VERSION 5.8 ;
BUSBITCHARS "[]" ;
DIVIDERCHAR "/" ;

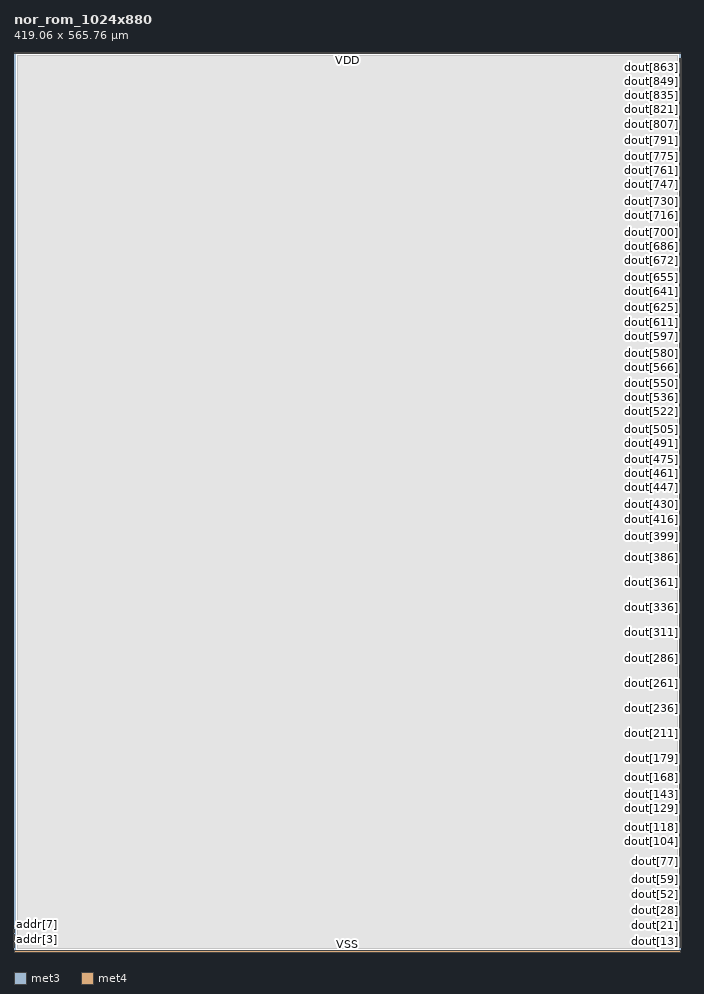
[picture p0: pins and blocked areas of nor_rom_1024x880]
MACRO nor_rom_1024x880
  CLASS BLOCK ;
  ORIGIN 0 0 ;
  SIZE 419.060 BY 565.760 ;
  SYMMETRY X Y ;

  PIN clk
    DIRECTION INPUT ;
    USE CLOCK ;
    PORT
      LAYER met3 ;
        RECT -0.500 3.000 0.500 3.280 ;
    END
  END clk

  PIN ce
    DIRECTION INPUT ;
    USE SIGNAL ;
    PORT
      LAYER met3 ;
        RECT -0.500 4.000 0.500 4.280 ;
    END
  END ce

  PIN addr[0]
    DIRECTION INPUT ;
    USE SIGNAL ;
    PORT
      LAYER met3 ;
        RECT -0.500 5.000 0.500 5.280 ;
    END
  END addr[0]

  PIN addr[1]
    DIRECTION INPUT ;
    USE SIGNAL ;
    PORT
      LAYER met3 ;
        RECT -0.500 6.000 0.500 6.280 ;
    END
  END addr[1]

  PIN addr[2]
    DIRECTION INPUT ;
    USE SIGNAL ;
    PORT
      LAYER met3 ;
        RECT -0.500 7.000 0.500 7.280 ;
    END
  END addr[2]

  PIN addr[3]
    DIRECTION INPUT ;
    USE SIGNAL ;
    PORT
      LAYER met3 ;
        RECT -0.500 8.000 0.500 8.280 ;
    END
  END addr[3]

  PIN addr[4]
    DIRECTION INPUT ;
    USE SIGNAL ;
    PORT
      LAYER met3 ;
        RECT -0.500 9.000 0.500 9.280 ;
    END
  END addr[4]

  PIN addr[5]
    DIRECTION INPUT ;
    USE SIGNAL ;
    PORT
      LAYER met3 ;
        RECT -0.500 10.000 0.500 10.280 ;
    END
  END addr[5]

  PIN addr[6]
    DIRECTION INPUT ;
    USE SIGNAL ;
    PORT
      LAYER met3 ;
        RECT -0.500 11.000 0.500 11.280 ;
    END
  END addr[6]

  PIN addr[7]
    DIRECTION INPUT ;
    USE SIGNAL ;
    PORT
      LAYER met3 ;
        RECT -0.500 12.000 0.500 12.280 ;
    END
  END addr[7]

  PIN addr[8]
    DIRECTION INPUT ;
    USE SIGNAL ;
    PORT
      LAYER met3 ;
        RECT -0.500 13.000 0.500 13.280 ;
    END
  END addr[8]

  PIN addr[9]
    DIRECTION INPUT ;
    USE SIGNAL ;
    PORT
      LAYER met3 ;
        RECT -0.500 14.000 0.500 14.280 ;
    END
  END addr[9]

  PIN dout[0]
    DIRECTION OUTPUT ;
    USE SIGNAL ;
    PORT
      LAYER met3 ;
        RECT 418.560 3.000 419.560 3.280 ;
    END
  END dout[0]

  PIN dout[1]
    DIRECTION OUTPUT ;
    USE SIGNAL ;
    PORT
      LAYER met3 ;
        RECT 418.560 3.635 419.560 3.915 ;
    END
  END dout[1]

  PIN dout[2]
    DIRECTION OUTPUT ;
    USE SIGNAL ;
    PORT
      LAYER met3 ;
        RECT 418.560 4.270 419.560 4.550 ;
    END
  END dout[2]

  PIN dout[3]
    DIRECTION OUTPUT ;
    USE SIGNAL ;
    PORT
      LAYER met3 ;
        RECT 418.560 4.905 419.560 5.185 ;
    END
  END dout[3]

  PIN dout[4]
    DIRECTION OUTPUT ;
    USE SIGNAL ;
    PORT
      LAYER met3 ;
        RECT 418.560 5.540 419.560 5.820 ;
    END
  END dout[4]

  PIN dout[5]
    DIRECTION OUTPUT ;
    USE SIGNAL ;
    PORT
      LAYER met3 ;
        RECT 418.560 6.175 419.560 6.455 ;
    END
  END dout[5]

  PIN dout[6]
    DIRECTION OUTPUT ;
    USE SIGNAL ;
    PORT
      LAYER met3 ;
        RECT 418.560 6.810 419.560 7.090 ;
    END
  END dout[6]

  PIN dout[7]
    DIRECTION OUTPUT ;
    USE SIGNAL ;
    PORT
      LAYER met3 ;
        RECT 418.560 7.445 419.560 7.725 ;
    END
  END dout[7]

  PIN dout[8]
    DIRECTION OUTPUT ;
    USE SIGNAL ;
    PORT
      LAYER met3 ;
        RECT 418.560 8.080 419.560 8.360 ;
    END
  END dout[8]

  PIN dout[9]
    DIRECTION OUTPUT ;
    USE SIGNAL ;
    PORT
      LAYER met3 ;
        RECT 418.560 8.715 419.560 8.995 ;
    END
  END dout[9]

  PIN dout[10]
    DIRECTION OUTPUT ;
    USE SIGNAL ;
    PORT
      LAYER met3 ;
        RECT 418.560 9.350 419.560 9.630 ;
    END
  END dout[10]

  PIN dout[11]
    DIRECTION OUTPUT ;
    USE SIGNAL ;
    PORT
      LAYER met3 ;
        RECT 418.560 9.985 419.560 10.265 ;
    END
  END dout[11]

  PIN dout[12]
    DIRECTION OUTPUT ;
    USE SIGNAL ;
    PORT
      LAYER met3 ;
        RECT 418.560 10.620 419.560 10.900 ;
    END
  END dout[12]

  PIN dout[13]
    DIRECTION OUTPUT ;
    USE SIGNAL ;
    PORT
      LAYER met3 ;
        RECT 418.560 11.255 419.560 11.535 ;
    END
  END dout[13]

  PIN dout[14]
    DIRECTION OUTPUT ;
    USE SIGNAL ;
    PORT
      LAYER met3 ;
        RECT 418.560 11.890 419.560 12.170 ;
    END
  END dout[14]

  PIN dout[15]
    DIRECTION OUTPUT ;
    USE SIGNAL ;
    PORT
      LAYER met3 ;
        RECT 418.560 12.525 419.560 12.805 ;
    END
  END dout[15]

  PIN dout[16]
    DIRECTION OUTPUT ;
    USE SIGNAL ;
    PORT
      LAYER met3 ;
        RECT 418.560 13.160 419.560 13.440 ;
    END
  END dout[16]

  PIN dout[17]
    DIRECTION OUTPUT ;
    USE SIGNAL ;
    PORT
      LAYER met3 ;
        RECT 418.560 13.795 419.560 14.075 ;
    END
  END dout[17]

  PIN dout[18]
    DIRECTION OUTPUT ;
    USE SIGNAL ;
    PORT
      LAYER met3 ;
        RECT 418.560 14.430 419.560 14.710 ;
    END
  END dout[18]

  PIN dout[19]
    DIRECTION OUTPUT ;
    USE SIGNAL ;
    PORT
      LAYER met3 ;
        RECT 418.560 15.065 419.560 15.345 ;
    END
  END dout[19]

  PIN dout[20]
    DIRECTION OUTPUT ;
    USE SIGNAL ;
    PORT
      LAYER met3 ;
        RECT 418.560 15.700 419.560 15.980 ;
    END
  END dout[20]

  PIN dout[21]
    DIRECTION OUTPUT ;
    USE SIGNAL ;
    PORT
      LAYER met3 ;
        RECT 418.560 16.335 419.560 16.615 ;
    END
  END dout[21]

  PIN dout[22]
    DIRECTION OUTPUT ;
    USE SIGNAL ;
    PORT
      LAYER met3 ;
        RECT 418.560 16.970 419.560 17.250 ;
    END
  END dout[22]

  PIN dout[23]
    DIRECTION OUTPUT ;
    USE SIGNAL ;
    PORT
      LAYER met3 ;
        RECT 418.560 17.605 419.560 17.885 ;
    END
  END dout[23]

  PIN dout[24]
    DIRECTION OUTPUT ;
    USE SIGNAL ;
    PORT
      LAYER met3 ;
        RECT 418.560 18.240 419.560 18.520 ;
    END
  END dout[24]

  PIN dout[25]
    DIRECTION OUTPUT ;
    USE SIGNAL ;
    PORT
      LAYER met3 ;
        RECT 418.560 18.875 419.560 19.155 ;
    END
  END dout[25]

  PIN dout[26]
    DIRECTION OUTPUT ;
    USE SIGNAL ;
    PORT
      LAYER met3 ;
        RECT 418.560 19.510 419.560 19.790 ;
    END
  END dout[26]

  PIN dout[27]
    DIRECTION OUTPUT ;
    USE SIGNAL ;
    PORT
      LAYER met3 ;
        RECT 418.560 20.145 419.560 20.425 ;
    END
  END dout[27]

  PIN dout[28]
    DIRECTION OUTPUT ;
    USE SIGNAL ;
    PORT
      LAYER met3 ;
        RECT 418.560 20.780 419.560 21.060 ;
    END
  END dout[28]

  PIN dout[29]
    DIRECTION OUTPUT ;
    USE SIGNAL ;
    PORT
      LAYER met3 ;
        RECT 418.560 21.415 419.560 21.695 ;
    END
  END dout[29]

  PIN dout[30]
    DIRECTION OUTPUT ;
    USE SIGNAL ;
    PORT
      LAYER met3 ;
        RECT 418.560 22.050 419.560 22.330 ;
    END
  END dout[30]

  PIN dout[31]
    DIRECTION OUTPUT ;
    USE SIGNAL ;
    PORT
      LAYER met3 ;
        RECT 418.560 22.685 419.560 22.965 ;
    END
  END dout[31]

  PIN dout[32]
    DIRECTION OUTPUT ;
    USE SIGNAL ;
    PORT
      LAYER met3 ;
        RECT 418.560 23.320 419.560 23.600 ;
    END
  END dout[32]

  PIN dout[33]
    DIRECTION OUTPUT ;
    USE SIGNAL ;
    PORT
      LAYER met3 ;
        RECT 418.560 23.955 419.560 24.235 ;
    END
  END dout[33]

  PIN dout[34]
    DIRECTION OUTPUT ;
    USE SIGNAL ;
    PORT
      LAYER met3 ;
        RECT 418.560 24.590 419.560 24.870 ;
    END
  END dout[34]

  PIN dout[35]
    DIRECTION OUTPUT ;
    USE SIGNAL ;
    PORT
      LAYER met3 ;
        RECT 418.560 25.225 419.560 25.505 ;
    END
  END dout[35]

  PIN dout[36]
    DIRECTION OUTPUT ;
    USE SIGNAL ;
    PORT
      LAYER met3 ;
        RECT 418.560 25.860 419.560 26.140 ;
    END
  END dout[36]

  PIN dout[37]
    DIRECTION OUTPUT ;
    USE SIGNAL ;
    PORT
      LAYER met3 ;
        RECT 418.560 26.495 419.560 26.775 ;
    END
  END dout[37]

  PIN dout[38]
    DIRECTION OUTPUT ;
    USE SIGNAL ;
    PORT
      LAYER met3 ;
        RECT 418.560 27.130 419.560 27.410 ;
    END
  END dout[38]

  PIN dout[39]
    DIRECTION OUTPUT ;
    USE SIGNAL ;
    PORT
      LAYER met3 ;
        RECT 418.560 27.765 419.560 28.045 ;
    END
  END dout[39]

  PIN dout[40]
    DIRECTION OUTPUT ;
    USE SIGNAL ;
    PORT
      LAYER met3 ;
        RECT 418.560 28.400 419.560 28.680 ;
    END
  END dout[40]

  PIN dout[41]
    DIRECTION OUTPUT ;
    USE SIGNAL ;
    PORT
      LAYER met3 ;
        RECT 418.560 29.035 419.560 29.315 ;
    END
  END dout[41]

  PIN dout[42]
    DIRECTION OUTPUT ;
    USE SIGNAL ;
    PORT
      LAYER met3 ;
        RECT 418.560 29.670 419.560 29.950 ;
    END
  END dout[42]

  PIN dout[43]
    DIRECTION OUTPUT ;
    USE SIGNAL ;
    PORT
      LAYER met3 ;
        RECT 418.560 30.305 419.560 30.585 ;
    END
  END dout[43]

  PIN dout[44]
    DIRECTION OUTPUT ;
    USE SIGNAL ;
    PORT
      LAYER met3 ;
        RECT 418.560 30.940 419.560 31.220 ;
    END
  END dout[44]

  PIN dout[45]
    DIRECTION OUTPUT ;
    USE SIGNAL ;
    PORT
      LAYER met3 ;
        RECT 418.560 31.575 419.560 31.855 ;
    END
  END dout[45]

  PIN dout[46]
    DIRECTION OUTPUT ;
    USE SIGNAL ;
    PORT
      LAYER met3 ;
        RECT 418.560 32.210 419.560 32.490 ;
    END
  END dout[46]

  PIN dout[47]
    DIRECTION OUTPUT ;
    USE SIGNAL ;
    PORT
      LAYER met3 ;
        RECT 418.560 32.845 419.560 33.125 ;
    END
  END dout[47]

  PIN dout[48]
    DIRECTION OUTPUT ;
    USE SIGNAL ;
    PORT
      LAYER met3 ;
        RECT 418.560 33.480 419.560 33.760 ;
    END
  END dout[48]

  PIN dout[49]
    DIRECTION OUTPUT ;
    USE SIGNAL ;
    PORT
      LAYER met3 ;
        RECT 418.560 34.115 419.560 34.395 ;
    END
  END dout[49]

  PIN dout[50]
    DIRECTION OUTPUT ;
    USE SIGNAL ;
    PORT
      LAYER met3 ;
        RECT 418.560 34.750 419.560 35.030 ;
    END
  END dout[50]

  PIN dout[51]
    DIRECTION OUTPUT ;
    USE SIGNAL ;
    PORT
      LAYER met3 ;
        RECT 418.560 35.385 419.560 35.665 ;
    END
  END dout[51]

  PIN dout[52]
    DIRECTION OUTPUT ;
    USE SIGNAL ;
    PORT
      LAYER met3 ;
        RECT 418.560 36.020 419.560 36.300 ;
    END
  END dout[52]

  PIN dout[53]
    DIRECTION OUTPUT ;
    USE SIGNAL ;
    PORT
      LAYER met3 ;
        RECT 418.560 36.655 419.560 36.935 ;
    END
  END dout[53]

  PIN dout[54]
    DIRECTION OUTPUT ;
    USE SIGNAL ;
    PORT
      LAYER met3 ;
        RECT 418.560 37.290 419.560 37.570 ;
    END
  END dout[54]

  PIN dout[55]
    DIRECTION OUTPUT ;
    USE SIGNAL ;
    PORT
      LAYER met3 ;
        RECT 418.560 37.925 419.560 38.205 ;
    END
  END dout[55]

  PIN dout[56]
    DIRECTION OUTPUT ;
    USE SIGNAL ;
    PORT
      LAYER met3 ;
        RECT 418.560 38.560 419.560 38.840 ;
    END
  END dout[56]

  PIN dout[57]
    DIRECTION OUTPUT ;
    USE SIGNAL ;
    PORT
      LAYER met3 ;
        RECT 418.560 39.195 419.560 39.475 ;
    END
  END dout[57]

  PIN dout[58]
    DIRECTION OUTPUT ;
    USE SIGNAL ;
    PORT
      LAYER met3 ;
        RECT 418.560 39.830 419.560 40.110 ;
    END
  END dout[58]

  PIN dout[59]
    DIRECTION OUTPUT ;
    USE SIGNAL ;
    PORT
      LAYER met3 ;
        RECT 418.560 40.465 419.560 40.745 ;
    END
  END dout[59]

  PIN dout[60]
    DIRECTION OUTPUT ;
    USE SIGNAL ;
    PORT
      LAYER met3 ;
        RECT 418.560 41.100 419.560 41.380 ;
    END
  END dout[60]

  PIN dout[61]
    DIRECTION OUTPUT ;
    USE SIGNAL ;
    PORT
      LAYER met3 ;
        RECT 418.560 41.735 419.560 42.015 ;
    END
  END dout[61]

  PIN dout[62]
    DIRECTION OUTPUT ;
    USE SIGNAL ;
    PORT
      LAYER met3 ;
        RECT 418.560 42.370 419.560 42.650 ;
    END
  END dout[62]

  PIN dout[63]
    DIRECTION OUTPUT ;
    USE SIGNAL ;
    PORT
      LAYER met3 ;
        RECT 418.560 43.005 419.560 43.285 ;
    END
  END dout[63]

  PIN dout[64]
    DIRECTION OUTPUT ;
    USE SIGNAL ;
    PORT
      LAYER met3 ;
        RECT 418.560 43.640 419.560 43.920 ;
    END
  END dout[64]

  PIN dout[65]
    DIRECTION OUTPUT ;
    USE SIGNAL ;
    PORT
      LAYER met3 ;
        RECT 418.560 44.275 419.560 44.555 ;
    END
  END dout[65]

  PIN dout[66]
    DIRECTION OUTPUT ;
    USE SIGNAL ;
    PORT
      LAYER met3 ;
        RECT 418.560 44.910 419.560 45.190 ;
    END
  END dout[66]

  PIN dout[67]
    DIRECTION OUTPUT ;
    USE SIGNAL ;
    PORT
      LAYER met3 ;
        RECT 418.560 45.545 419.560 45.825 ;
    END
  END dout[67]

  PIN dout[68]
    DIRECTION OUTPUT ;
    USE SIGNAL ;
    PORT
      LAYER met3 ;
        RECT 418.560 46.180 419.560 46.460 ;
    END
  END dout[68]

  PIN dout[69]
    DIRECTION OUTPUT ;
    USE SIGNAL ;
    PORT
      LAYER met3 ;
        RECT 418.560 46.815 419.560 47.095 ;
    END
  END dout[69]

  PIN dout[70]
    DIRECTION OUTPUT ;
    USE SIGNAL ;
    PORT
      LAYER met3 ;
        RECT 418.560 47.450 419.560 47.730 ;
    END
  END dout[70]

  PIN dout[71]
    DIRECTION OUTPUT ;
    USE SIGNAL ;
    PORT
      LAYER met3 ;
        RECT 418.560 48.085 419.560 48.365 ;
    END
  END dout[71]

  PIN dout[72]
    DIRECTION OUTPUT ;
    USE SIGNAL ;
    PORT
      LAYER met3 ;
        RECT 418.560 48.720 419.560 49.000 ;
    END
  END dout[72]

  PIN dout[73]
    DIRECTION OUTPUT ;
    USE SIGNAL ;
    PORT
      LAYER met3 ;
        RECT 418.560 49.355 419.560 49.635 ;
    END
  END dout[73]

  PIN dout[74]
    DIRECTION OUTPUT ;
    USE SIGNAL ;
    PORT
      LAYER met3 ;
        RECT 418.560 49.990 419.560 50.270 ;
    END
  END dout[74]

  PIN dout[75]
    DIRECTION OUTPUT ;
    USE SIGNAL ;
    PORT
      LAYER met3 ;
        RECT 418.560 50.625 419.560 50.905 ;
    END
  END dout[75]

  PIN dout[76]
    DIRECTION OUTPUT ;
    USE SIGNAL ;
    PORT
      LAYER met3 ;
        RECT 418.560 51.260 419.560 51.540 ;
    END
  END dout[76]

  PIN dout[77]
    DIRECTION OUTPUT ;
    USE SIGNAL ;
    PORT
      LAYER met3 ;
        RECT 418.560 51.895 419.560 52.175 ;
    END
  END dout[77]

  PIN dout[78]
    DIRECTION OUTPUT ;
    USE SIGNAL ;
    PORT
      LAYER met3 ;
        RECT 418.560 52.530 419.560 52.810 ;
    END
  END dout[78]

  PIN dout[79]
    DIRECTION OUTPUT ;
    USE SIGNAL ;
    PORT
      LAYER met3 ;
        RECT 418.560 53.165 419.560 53.445 ;
    END
  END dout[79]

  PIN dout[80]
    DIRECTION OUTPUT ;
    USE SIGNAL ;
    PORT
      LAYER met3 ;
        RECT 418.560 53.800 419.560 54.080 ;
    END
  END dout[80]

  PIN dout[81]
    DIRECTION OUTPUT ;
    USE SIGNAL ;
    PORT
      LAYER met3 ;
        RECT 418.560 54.435 419.560 54.715 ;
    END
  END dout[81]

  PIN dout[82]
    DIRECTION OUTPUT ;
    USE SIGNAL ;
    PORT
      LAYER met3 ;
        RECT 418.560 55.070 419.560 55.350 ;
    END
  END dout[82]

  PIN dout[83]
    DIRECTION OUTPUT ;
    USE SIGNAL ;
    PORT
      LAYER met3 ;
        RECT 418.560 55.705 419.560 55.985 ;
    END
  END dout[83]

  PIN dout[84]
    DIRECTION OUTPUT ;
    USE SIGNAL ;
    PORT
      LAYER met3 ;
        RECT 418.560 56.340 419.560 56.620 ;
    END
  END dout[84]

  PIN dout[85]
    DIRECTION OUTPUT ;
    USE SIGNAL ;
    PORT
      LAYER met3 ;
        RECT 418.560 56.975 419.560 57.255 ;
    END
  END dout[85]

  PIN dout[86]
    DIRECTION OUTPUT ;
    USE SIGNAL ;
    PORT
      LAYER met3 ;
        RECT 418.560 57.610 419.560 57.890 ;
    END
  END dout[86]

  PIN dout[87]
    DIRECTION OUTPUT ;
    USE SIGNAL ;
    PORT
      LAYER met3 ;
        RECT 418.560 58.245 419.560 58.525 ;
    END
  END dout[87]

  PIN dout[88]
    DIRECTION OUTPUT ;
    USE SIGNAL ;
    PORT
      LAYER met3 ;
        RECT 418.560 58.880 419.560 59.160 ;
    END
  END dout[88]

  PIN dout[89]
    DIRECTION OUTPUT ;
    USE SIGNAL ;
    PORT
      LAYER met3 ;
        RECT 418.560 59.515 419.560 59.795 ;
    END
  END dout[89]

  PIN dout[90]
    DIRECTION OUTPUT ;
    USE SIGNAL ;
    PORT
      LAYER met3 ;
        RECT 418.560 60.150 419.560 60.430 ;
    END
  END dout[90]

  PIN dout[91]
    DIRECTION OUTPUT ;
    USE SIGNAL ;
    PORT
      LAYER met3 ;
        RECT 418.560 60.785 419.560 61.065 ;
    END
  END dout[91]

  PIN dout[92]
    DIRECTION OUTPUT ;
    USE SIGNAL ;
    PORT
      LAYER met3 ;
        RECT 418.560 61.420 419.560 61.700 ;
    END
  END dout[92]

  PIN dout[93]
    DIRECTION OUTPUT ;
    USE SIGNAL ;
    PORT
      LAYER met3 ;
        RECT 418.560 62.055 419.560 62.335 ;
    END
  END dout[93]

  PIN dout[94]
    DIRECTION OUTPUT ;
    USE SIGNAL ;
    PORT
      LAYER met3 ;
        RECT 418.560 62.690 419.560 62.970 ;
    END
  END dout[94]

  PIN dout[95]
    DIRECTION OUTPUT ;
    USE SIGNAL ;
    PORT
      LAYER met3 ;
        RECT 418.560 63.325 419.560 63.605 ;
    END
  END dout[95]

  PIN dout[96]
    DIRECTION OUTPUT ;
    USE SIGNAL ;
    PORT
      LAYER met3 ;
        RECT 418.560 63.960 419.560 64.240 ;
    END
  END dout[96]

  PIN dout[97]
    DIRECTION OUTPUT ;
    USE SIGNAL ;
    PORT
      LAYER met3 ;
        RECT 418.560 64.595 419.560 64.875 ;
    END
  END dout[97]

  PIN dout[98]
    DIRECTION OUTPUT ;
    USE SIGNAL ;
    PORT
      LAYER met3 ;
        RECT 418.560 65.230 419.560 65.510 ;
    END
  END dout[98]

  PIN dout[99]
    DIRECTION OUTPUT ;
    USE SIGNAL ;
    PORT
      LAYER met3 ;
        RECT 418.560 65.865 419.560 66.145 ;
    END
  END dout[99]

  PIN dout[100]
    DIRECTION OUTPUT ;
    USE SIGNAL ;
    PORT
      LAYER met3 ;
        RECT 418.560 66.500 419.560 66.780 ;
    END
  END dout[100]

  PIN dout[101]
    DIRECTION OUTPUT ;
    USE SIGNAL ;
    PORT
      LAYER met3 ;
        RECT 418.560 67.135 419.560 67.415 ;
    END
  END dout[101]

  PIN dout[102]
    DIRECTION OUTPUT ;
    USE SIGNAL ;
    PORT
      LAYER met3 ;
        RECT 418.560 67.770 419.560 68.050 ;
    END
  END dout[102]

  PIN dout[103]
    DIRECTION OUTPUT ;
    USE SIGNAL ;
    PORT
      LAYER met3 ;
        RECT 418.560 68.405 419.560 68.685 ;
    END
  END dout[103]

  PIN dout[104]
    DIRECTION OUTPUT ;
    USE SIGNAL ;
    PORT
      LAYER met3 ;
        RECT 418.560 69.040 419.560 69.320 ;
    END
  END dout[104]

  PIN dout[105]
    DIRECTION OUTPUT ;
    USE SIGNAL ;
    PORT
      LAYER met3 ;
        RECT 418.560 69.675 419.560 69.955 ;
    END
  END dout[105]

  PIN dout[106]
    DIRECTION OUTPUT ;
    USE SIGNAL ;
    PORT
      LAYER met3 ;
        RECT 418.560 70.310 419.560 70.590 ;
    END
  END dout[106]

  PIN dout[107]
    DIRECTION OUTPUT ;
    USE SIGNAL ;
    PORT
      LAYER met3 ;
        RECT 418.560 70.945 419.560 71.225 ;
    END
  END dout[107]

  PIN dout[108]
    DIRECTION OUTPUT ;
    USE SIGNAL ;
    PORT
      LAYER met3 ;
        RECT 418.560 71.580 419.560 71.860 ;
    END
  END dout[108]

  PIN dout[109]
    DIRECTION OUTPUT ;
    USE SIGNAL ;
    PORT
      LAYER met3 ;
        RECT 418.560 72.215 419.560 72.495 ;
    END
  END dout[109]

  PIN dout[110]
    DIRECTION OUTPUT ;
    USE SIGNAL ;
    PORT
      LAYER met3 ;
        RECT 418.560 72.850 419.560 73.130 ;
    END
  END dout[110]

  PIN dout[111]
    DIRECTION OUTPUT ;
    USE SIGNAL ;
    PORT
      LAYER met3 ;
        RECT 418.560 73.485 419.560 73.765 ;
    END
  END dout[111]

  PIN dout[112]
    DIRECTION OUTPUT ;
    USE SIGNAL ;
    PORT
      LAYER met3 ;
        RECT 418.560 74.120 419.560 74.400 ;
    END
  END dout[112]

  PIN dout[113]
    DIRECTION OUTPUT ;
    USE SIGNAL ;
    PORT
      LAYER met3 ;
        RECT 418.560 74.755 419.560 75.035 ;
    END
  END dout[113]

  PIN dout[114]
    DIRECTION OUTPUT ;
    USE SIGNAL ;
    PORT
      LAYER met3 ;
        RECT 418.560 75.390 419.560 75.670 ;
    END
  END dout[114]

  PIN dout[115]
    DIRECTION OUTPUT ;
    USE SIGNAL ;
    PORT
      LAYER met3 ;
        RECT 418.560 76.025 419.560 76.305 ;
    END
  END dout[115]

  PIN dout[116]
    DIRECTION OUTPUT ;
    USE SIGNAL ;
    PORT
      LAYER met3 ;
        RECT 418.560 76.660 419.560 76.940 ;
    END
  END dout[116]

  PIN dout[117]
    DIRECTION OUTPUT ;
    USE SIGNAL ;
    PORT
      LAYER met3 ;
        RECT 418.560 77.295 419.560 77.575 ;
    END
  END dout[117]

  PIN dout[118]
    DIRECTION OUTPUT ;
    USE SIGNAL ;
    PORT
      LAYER met3 ;
        RECT 418.560 77.930 419.560 78.210 ;
    END
  END dout[118]

  PIN dout[119]
    DIRECTION OUTPUT ;
    USE SIGNAL ;
    PORT
      LAYER met3 ;
        RECT 418.560 78.565 419.560 78.845 ;
    END
  END dout[119]

  PIN dout[120]
    DIRECTION OUTPUT ;
    USE SIGNAL ;
    PORT
      LAYER met3 ;
        RECT 418.560 79.200 419.560 79.480 ;
    END
  END dout[120]

  PIN dout[121]
    DIRECTION OUTPUT ;
    USE SIGNAL ;
    PORT
      LAYER met3 ;
        RECT 418.560 79.835 419.560 80.115 ;
    END
  END dout[121]

  PIN dout[122]
    DIRECTION OUTPUT ;
    USE SIGNAL ;
    PORT
      LAYER met3 ;
        RECT 418.560 80.470 419.560 80.750 ;
    END
  END dout[122]

  PIN dout[123]
    DIRECTION OUTPUT ;
    USE SIGNAL ;
    PORT
      LAYER met3 ;
        RECT 418.560 81.105 419.560 81.385 ;
    END
  END dout[123]

  PIN dout[124]
    DIRECTION OUTPUT ;
    USE SIGNAL ;
    PORT
      LAYER met3 ;
        RECT 418.560 81.740 419.560 82.020 ;
    END
  END dout[124]

  PIN dout[125]
    DIRECTION OUTPUT ;
    USE SIGNAL ;
    PORT
      LAYER met3 ;
        RECT 418.560 82.375 419.560 82.655 ;
    END
  END dout[125]

  PIN dout[126]
    DIRECTION OUTPUT ;
    USE SIGNAL ;
    PORT
      LAYER met3 ;
        RECT 418.560 83.010 419.560 83.290 ;
    END
  END dout[126]

  PIN dout[127]
    DIRECTION OUTPUT ;
    USE SIGNAL ;
    PORT
      LAYER met3 ;
        RECT 418.560 83.645 419.560 83.925 ;
    END
  END dout[127]

  PIN dout[128]
    DIRECTION OUTPUT ;
    USE SIGNAL ;
    PORT
      LAYER met3 ;
        RECT 418.560 84.280 419.560 84.560 ;
    END
  END dout[128]

  PIN dout[129]
    DIRECTION OUTPUT ;
    USE SIGNAL ;
    PORT
      LAYER met3 ;
        RECT 418.560 84.915 419.560 85.195 ;
    END
  END dout[129]

  PIN dout[130]
    DIRECTION OUTPUT ;
    USE SIGNAL ;
    PORT
      LAYER met3 ;
        RECT 418.560 85.550 419.560 85.830 ;
    END
  END dout[130]

  PIN dout[131]
    DIRECTION OUTPUT ;
    USE SIGNAL ;
    PORT
      LAYER met3 ;
        RECT 418.560 86.185 419.560 86.465 ;
    END
  END dout[131]

  PIN dout[132]
    DIRECTION OUTPUT ;
    USE SIGNAL ;
    PORT
      LAYER met3 ;
        RECT 418.560 86.820 419.560 87.100 ;
    END
  END dout[132]

  PIN dout[133]
    DIRECTION OUTPUT ;
    USE SIGNAL ;
    PORT
      LAYER met3 ;
        RECT 418.560 87.455 419.560 87.735 ;
    END
  END dout[133]

  PIN dout[134]
    DIRECTION OUTPUT ;
    USE SIGNAL ;
    PORT
      LAYER met3 ;
        RECT 418.560 88.090 419.560 88.370 ;
    END
  END dout[134]

  PIN dout[135]
    DIRECTION OUTPUT ;
    USE SIGNAL ;
    PORT
      LAYER met3 ;
        RECT 418.560 88.725 419.560 89.005 ;
    END
  END dout[135]

  PIN dout[136]
    DIRECTION OUTPUT ;
    USE SIGNAL ;
    PORT
      LAYER met3 ;
        RECT 418.560 89.360 419.560 89.640 ;
    END
  END dout[136]

  PIN dout[137]
    DIRECTION OUTPUT ;
    USE SIGNAL ;
    PORT
      LAYER met3 ;
        RECT 418.560 89.995 419.560 90.275 ;
    END
  END dout[137]

  PIN dout[138]
    DIRECTION OUTPUT ;
    USE SIGNAL ;
    PORT
      LAYER met3 ;
        RECT 418.560 90.630 419.560 90.910 ;
    END
  END dout[138]

  PIN dout[139]
    DIRECTION OUTPUT ;
    USE SIGNAL ;
    PORT
      LAYER met3 ;
        RECT 418.560 91.265 419.560 91.545 ;
    END
  END dout[139]

  PIN dout[140]
    DIRECTION OUTPUT ;
    USE SIGNAL ;
    PORT
      LAYER met3 ;
        RECT 418.560 91.900 419.560 92.180 ;
    END
  END dout[140]

  PIN dout[141]
    DIRECTION OUTPUT ;
    USE SIGNAL ;
    PORT
      LAYER met3 ;
        RECT 418.560 92.535 419.560 92.815 ;
    END
  END dout[141]

  PIN dout[142]
    DIRECTION OUTPUT ;
    USE SIGNAL ;
    PORT
      LAYER met3 ;
        RECT 418.560 93.170 419.560 93.450 ;
    END
  END dout[142]

  PIN dout[143]
    DIRECTION OUTPUT ;
    USE SIGNAL ;
    PORT
      LAYER met3 ;
        RECT 418.560 93.805 419.560 94.085 ;
    END
  END dout[143]

  PIN dout[144]
    DIRECTION OUTPUT ;
    USE SIGNAL ;
    PORT
      LAYER met3 ;
        RECT 418.560 94.440 419.560 94.720 ;
    END
  END dout[144]

  PIN dout[145]
    DIRECTION OUTPUT ;
    USE SIGNAL ;
    PORT
      LAYER met3 ;
        RECT 418.560 95.075 419.560 95.355 ;
    END
  END dout[145]

  PIN dout[146]
    DIRECTION OUTPUT ;
    USE SIGNAL ;
    PORT
      LAYER met3 ;
        RECT 418.560 95.710 419.560 95.990 ;
    END
  END dout[146]

  PIN dout[147]
    DIRECTION OUTPUT ;
    USE SIGNAL ;
    PORT
      LAYER met3 ;
        RECT 418.560 96.345 419.560 96.625 ;
    END
  END dout[147]

  PIN dout[148]
    DIRECTION OUTPUT ;
    USE SIGNAL ;
    PORT
      LAYER met3 ;
        RECT 418.560 96.980 419.560 97.260 ;
    END
  END dout[148]

  PIN dout[149]
    DIRECTION OUTPUT ;
    USE SIGNAL ;
    PORT
      LAYER met3 ;
        RECT 418.560 97.615 419.560 97.895 ;
    END
  END dout[149]

  PIN dout[150]
    DIRECTION OUTPUT ;
    USE SIGNAL ;
    PORT
      LAYER met3 ;
        RECT 418.560 98.250 419.560 98.530 ;
    END
  END dout[150]

  PIN dout[151]
    DIRECTION OUTPUT ;
    USE SIGNAL ;
    PORT
      LAYER met3 ;
        RECT 418.560 98.885 419.560 99.165 ;
    END
  END dout[151]

  PIN dout[152]
    DIRECTION OUTPUT ;
    USE SIGNAL ;
    PORT
      LAYER met3 ;
        RECT 418.560 99.520 419.560 99.800 ;
    END
  END dout[152]

  PIN dout[153]
    DIRECTION OUTPUT ;
    USE SIGNAL ;
    PORT
      LAYER met3 ;
        RECT 418.560 100.155 419.560 100.435 ;
    END
  END dout[153]

  PIN dout[154]
    DIRECTION OUTPUT ;
    USE SIGNAL ;
    PORT
      LAYER met3 ;
        RECT 418.560 100.790 419.560 101.070 ;
    END
  END dout[154]

  PIN dout[155]
    DIRECTION OUTPUT ;
    USE SIGNAL ;
    PORT
      LAYER met3 ;
        RECT 418.560 101.425 419.560 101.705 ;
    END
  END dout[155]

  PIN dout[156]
    DIRECTION OUTPUT ;
    USE SIGNAL ;
    PORT
      LAYER met3 ;
        RECT 418.560 102.060 419.560 102.340 ;
    END
  END dout[156]

  PIN dout[157]
    DIRECTION OUTPUT ;
    USE SIGNAL ;
    PORT
      LAYER met3 ;
        RECT 418.560 102.695 419.560 102.975 ;
    END
  END dout[157]

  PIN dout[158]
    DIRECTION OUTPUT ;
    USE SIGNAL ;
    PORT
      LAYER met3 ;
        RECT 418.560 103.330 419.560 103.610 ;
    END
  END dout[158]

  PIN dout[159]
    DIRECTION OUTPUT ;
    USE SIGNAL ;
    PORT
      LAYER met3 ;
        RECT 418.560 103.965 419.560 104.245 ;
    END
  END dout[159]

  PIN dout[160]
    DIRECTION OUTPUT ;
    USE SIGNAL ;
    PORT
      LAYER met3 ;
        RECT 418.560 104.600 419.560 104.880 ;
    END
  END dout[160]

  PIN dout[161]
    DIRECTION OUTPUT ;
    USE SIGNAL ;
    PORT
      LAYER met3 ;
        RECT 418.560 105.235 419.560 105.515 ;
    END
  END dout[161]

  PIN dout[162]
    DIRECTION OUTPUT ;
    USE SIGNAL ;
    PORT
      LAYER met3 ;
        RECT 418.560 105.870 419.560 106.150 ;
    END
  END dout[162]

  PIN dout[163]
    DIRECTION OUTPUT ;
    USE SIGNAL ;
    PORT
      LAYER met3 ;
        RECT 418.560 106.505 419.560 106.785 ;
    END
  END dout[163]

  PIN dout[164]
    DIRECTION OUTPUT ;
    USE SIGNAL ;
    PORT
      LAYER met3 ;
        RECT 418.560 107.140 419.560 107.420 ;
    END
  END dout[164]

  PIN dout[165]
    DIRECTION OUTPUT ;
    USE SIGNAL ;
    PORT
      LAYER met3 ;
        RECT 418.560 107.775 419.560 108.055 ;
    END
  END dout[165]

  PIN dout[166]
    DIRECTION OUTPUT ;
    USE SIGNAL ;
    PORT
      LAYER met3 ;
        RECT 418.560 108.410 419.560 108.690 ;
    END
  END dout[166]

  PIN dout[167]
    DIRECTION OUTPUT ;
    USE SIGNAL ;
    PORT
      LAYER met3 ;
        RECT 418.560 109.045 419.560 109.325 ;
    END
  END dout[167]

  PIN dout[168]
    DIRECTION OUTPUT ;
    USE SIGNAL ;
    PORT
      LAYER met3 ;
        RECT 418.560 109.680 419.560 109.960 ;
    END
  END dout[168]

  PIN dout[169]
    DIRECTION OUTPUT ;
    USE SIGNAL ;
    PORT
      LAYER met3 ;
        RECT 418.560 110.315 419.560 110.595 ;
    END
  END dout[169]

  PIN dout[170]
    DIRECTION OUTPUT ;
    USE SIGNAL ;
    PORT
      LAYER met3 ;
        RECT 418.560 110.950 419.560 111.230 ;
    END
  END dout[170]

  PIN dout[171]
    DIRECTION OUTPUT ;
    USE SIGNAL ;
    PORT
      LAYER met3 ;
        RECT 418.560 111.585 419.560 111.865 ;
    END
  END dout[171]

  PIN dout[172]
    DIRECTION OUTPUT ;
    USE SIGNAL ;
    PORT
      LAYER met3 ;
        RECT 418.560 112.220 419.560 112.500 ;
    END
  END dout[172]

  PIN dout[173]
    DIRECTION OUTPUT ;
    USE SIGNAL ;
    PORT
      LAYER met3 ;
        RECT 418.560 112.855 419.560 113.135 ;
    END
  END dout[173]

  PIN dout[174]
    DIRECTION OUTPUT ;
    USE SIGNAL ;
    PORT
      LAYER met3 ;
        RECT 418.560 113.490 419.560 113.770 ;
    END
  END dout[174]

  PIN dout[175]
    DIRECTION OUTPUT ;
    USE SIGNAL ;
    PORT
      LAYER met3 ;
        RECT 418.560 114.125 419.560 114.405 ;
    END
  END dout[175]

  PIN dout[176]
    DIRECTION OUTPUT ;
    USE SIGNAL ;
    PORT
      LAYER met3 ;
        RECT 418.560 114.760 419.560 115.040 ;
    END
  END dout[176]

  PIN dout[177]
    DIRECTION OUTPUT ;
    USE SIGNAL ;
    PORT
      LAYER met3 ;
        RECT 418.560 115.395 419.560 115.675 ;
    END
  END dout[177]

  PIN dout[178]
    DIRECTION OUTPUT ;
    USE SIGNAL ;
    PORT
      LAYER met3 ;
        RECT 418.560 116.030 419.560 116.310 ;
    END
  END dout[178]

  PIN dout[179]
    DIRECTION OUTPUT ;
    USE SIGNAL ;
    PORT
      LAYER met3 ;
        RECT 418.560 116.665 419.560 116.945 ;
    END
  END dout[179]

  PIN dout[180]
    DIRECTION OUTPUT ;
    USE SIGNAL ;
    PORT
      LAYER met3 ;
        RECT 418.560 117.300 419.560 117.580 ;
    END
  END dout[180]

  PIN dout[181]
    DIRECTION OUTPUT ;
    USE SIGNAL ;
    PORT
      LAYER met3 ;
        RECT 418.560 117.935 419.560 118.215 ;
    END
  END dout[181]

  PIN dout[182]
    DIRECTION OUTPUT ;
    USE SIGNAL ;
    PORT
      LAYER met3 ;
        RECT 418.560 118.570 419.560 118.850 ;
    END
  END dout[182]

  PIN dout[183]
    DIRECTION OUTPUT ;
    USE SIGNAL ;
    PORT
      LAYER met3 ;
        RECT 418.560 119.205 419.560 119.485 ;
    END
  END dout[183]

  PIN dout[184]
    DIRECTION OUTPUT ;
    USE SIGNAL ;
    PORT
      LAYER met3 ;
        RECT 418.560 119.840 419.560 120.120 ;
    END
  END dout[184]

  PIN dout[185]
    DIRECTION OUTPUT ;
    USE SIGNAL ;
    PORT
      LAYER met3 ;
        RECT 418.560 120.475 419.560 120.755 ;
    END
  END dout[185]

  PIN dout[186]
    DIRECTION OUTPUT ;
    USE SIGNAL ;
    PORT
      LAYER met3 ;
        RECT 418.560 121.110 419.560 121.390 ;
    END
  END dout[186]

  PIN dout[187]
    DIRECTION OUTPUT ;
    USE SIGNAL ;
    PORT
      LAYER met3 ;
        RECT 418.560 121.745 419.560 122.025 ;
    END
  END dout[187]

  PIN dout[188]
    DIRECTION OUTPUT ;
    USE SIGNAL ;
    PORT
      LAYER met3 ;
        RECT 418.560 122.380 419.560 122.660 ;
    END
  END dout[188]

  PIN dout[189]
    DIRECTION OUTPUT ;
    USE SIGNAL ;
    PORT
      LAYER met3 ;
        RECT 418.560 123.015 419.560 123.295 ;
    END
  END dout[189]

  PIN dout[190]
    DIRECTION OUTPUT ;
    USE SIGNAL ;
    PORT
      LAYER met3 ;
        RECT 418.560 123.650 419.560 123.930 ;
    END
  END dout[190]

  PIN dout[191]
    DIRECTION OUTPUT ;
    USE SIGNAL ;
    PORT
      LAYER met3 ;
        RECT 418.560 124.285 419.560 124.565 ;
    END
  END dout[191]

  PIN dout[192]
    DIRECTION OUTPUT ;
    USE SIGNAL ;
    PORT
      LAYER met3 ;
        RECT 418.560 124.920 419.560 125.200 ;
    END
  END dout[192]

  PIN dout[193]
    DIRECTION OUTPUT ;
    USE SIGNAL ;
    PORT
      LAYER met3 ;
        RECT 418.560 125.555 419.560 125.835 ;
    END
  END dout[193]

  PIN dout[194]
    DIRECTION OUTPUT ;
    USE SIGNAL ;
    PORT
      LAYER met3 ;
        RECT 418.560 126.190 419.560 126.470 ;
    END
  END dout[194]

  PIN dout[195]
    DIRECTION OUTPUT ;
    USE SIGNAL ;
    PORT
      LAYER met3 ;
        RECT 418.560 126.825 419.560 127.105 ;
    END
  END dout[195]

  PIN dout[196]
    DIRECTION OUTPUT ;
    USE SIGNAL ;
    PORT
      LAYER met3 ;
        RECT 418.560 127.460 419.560 127.740 ;
    END
  END dout[196]

  PIN dout[197]
    DIRECTION OUTPUT ;
    USE SIGNAL ;
    PORT
      LAYER met3 ;
        RECT 418.560 128.095 419.560 128.375 ;
    END
  END dout[197]

  PIN dout[198]
    DIRECTION OUTPUT ;
    USE SIGNAL ;
    PORT
      LAYER met3 ;
        RECT 418.560 128.730 419.560 129.010 ;
    END
  END dout[198]

  PIN dout[199]
    DIRECTION OUTPUT ;
    USE SIGNAL ;
    PORT
      LAYER met3 ;
        RECT 418.560 129.365 419.560 129.645 ;
    END
  END dout[199]

  PIN dout[200]
    DIRECTION OUTPUT ;
    USE SIGNAL ;
    PORT
      LAYER met3 ;
        RECT 418.560 130.000 419.560 130.280 ;
    END
  END dout[200]

  PIN dout[201]
    DIRECTION OUTPUT ;
    USE SIGNAL ;
    PORT
      LAYER met3 ;
        RECT 418.560 130.635 419.560 130.915 ;
    END
  END dout[201]

  PIN dout[202]
    DIRECTION OUTPUT ;
    USE SIGNAL ;
    PORT
      LAYER met3 ;
        RECT 418.560 131.270 419.560 131.550 ;
    END
  END dout[202]

  PIN dout[203]
    DIRECTION OUTPUT ;
    USE SIGNAL ;
    PORT
      LAYER met3 ;
        RECT 418.560 131.905 419.560 132.185 ;
    END
  END dout[203]

  PIN dout[204]
    DIRECTION OUTPUT ;
    USE SIGNAL ;
    PORT
      LAYER met3 ;
        RECT 418.560 132.540 419.560 132.820 ;
    END
  END dout[204]

  PIN dout[205]
    DIRECTION OUTPUT ;
    USE SIGNAL ;
    PORT
      LAYER met3 ;
        RECT 418.560 133.175 419.560 133.455 ;
    END
  END dout[205]

  PIN dout[206]
    DIRECTION OUTPUT ;
    USE SIGNAL ;
    PORT
      LAYER met3 ;
        RECT 418.560 133.810 419.560 134.090 ;
    END
  END dout[206]

  PIN dout[207]
    DIRECTION OUTPUT ;
    USE SIGNAL ;
    PORT
      LAYER met3 ;
        RECT 418.560 134.445 419.560 134.725 ;
    END
  END dout[207]

  PIN dout[208]
    DIRECTION OUTPUT ;
    USE SIGNAL ;
    PORT
      LAYER met3 ;
        RECT 418.560 135.080 419.560 135.360 ;
    END
  END dout[208]

  PIN dout[209]
    DIRECTION OUTPUT ;
    USE SIGNAL ;
    PORT
      LAYER met3 ;
        RECT 418.560 135.715 419.560 135.995 ;
    END
  END dout[209]

  PIN dout[210]
    DIRECTION OUTPUT ;
    USE SIGNAL ;
    PORT
      LAYER met3 ;
        RECT 418.560 136.350 419.560 136.630 ;
    END
  END dout[210]

  PIN dout[211]
    DIRECTION OUTPUT ;
    USE SIGNAL ;
    PORT
      LAYER met3 ;
        RECT 418.560 136.985 419.560 137.265 ;
    END
  END dout[211]

  PIN dout[212]
    DIRECTION OUTPUT ;
    USE SIGNAL ;
    PORT
      LAYER met3 ;
        RECT 418.560 137.620 419.560 137.900 ;
    END
  END dout[212]

  PIN dout[213]
    DIRECTION OUTPUT ;
    USE SIGNAL ;
    PORT
      LAYER met3 ;
        RECT 418.560 138.255 419.560 138.535 ;
    END
  END dout[213]

  PIN dout[214]
    DIRECTION OUTPUT ;
    USE SIGNAL ;
    PORT
      LAYER met3 ;
        RECT 418.560 138.890 419.560 139.170 ;
    END
  END dout[214]

  PIN dout[215]
    DIRECTION OUTPUT ;
    USE SIGNAL ;
    PORT
      LAYER met3 ;
        RECT 418.560 139.525 419.560 139.805 ;
    END
  END dout[215]

  PIN dout[216]
    DIRECTION OUTPUT ;
    USE SIGNAL ;
    PORT
      LAYER met3 ;
        RECT 418.560 140.160 419.560 140.440 ;
    END
  END dout[216]

  PIN dout[217]
    DIRECTION OUTPUT ;
    USE SIGNAL ;
    PORT
      LAYER met3 ;
        RECT 418.560 140.795 419.560 141.075 ;
    END
  END dout[217]

  PIN dout[218]
    DIRECTION OUTPUT ;
    USE SIGNAL ;
    PORT
      LAYER met3 ;
        RECT 418.560 141.430 419.560 141.710 ;
    END
  END dout[218]

  PIN dout[219]
    DIRECTION OUTPUT ;
    USE SIGNAL ;
    PORT
      LAYER met3 ;
        RECT 418.560 142.065 419.560 142.345 ;
    END
  END dout[219]

  PIN dout[220]
    DIRECTION OUTPUT ;
    USE SIGNAL ;
    PORT
      LAYER met3 ;
        RECT 418.560 142.700 419.560 142.980 ;
    END
  END dout[220]

  PIN dout[221]
    DIRECTION OUTPUT ;
    USE SIGNAL ;
    PORT
      LAYER met3 ;
        RECT 418.560 143.335 419.560 143.615 ;
    END
  END dout[221]

  PIN dout[222]
    DIRECTION OUTPUT ;
    USE SIGNAL ;
    PORT
      LAYER met3 ;
        RECT 418.560 143.970 419.560 144.250 ;
    END
  END dout[222]

  PIN dout[223]
    DIRECTION OUTPUT ;
    USE SIGNAL ;
    PORT
      LAYER met3 ;
        RECT 418.560 144.605 419.560 144.885 ;
    END
  END dout[223]

  PIN dout[224]
    DIRECTION OUTPUT ;
    USE SIGNAL ;
    PORT
      LAYER met3 ;
        RECT 418.560 145.240 419.560 145.520 ;
    END
  END dout[224]

  PIN dout[225]
    DIRECTION OUTPUT ;
    USE SIGNAL ;
    PORT
      LAYER met3 ;
        RECT 418.560 145.875 419.560 146.155 ;
    END
  END dout[225]

  PIN dout[226]
    DIRECTION OUTPUT ;
    USE SIGNAL ;
    PORT
      LAYER met3 ;
        RECT 418.560 146.510 419.560 146.790 ;
    END
  END dout[226]

  PIN dout[227]
    DIRECTION OUTPUT ;
    USE SIGNAL ;
    PORT
      LAYER met3 ;
        RECT 418.560 147.145 419.560 147.425 ;
    END
  END dout[227]

  PIN dout[228]
    DIRECTION OUTPUT ;
    USE SIGNAL ;
    PORT
      LAYER met3 ;
        RECT 418.560 147.780 419.560 148.060 ;
    END
  END dout[228]

  PIN dout[229]
    DIRECTION OUTPUT ;
    USE SIGNAL ;
    PORT
      LAYER met3 ;
        RECT 418.560 148.415 419.560 148.695 ;
    END
  END dout[229]

  PIN dout[230]
    DIRECTION OUTPUT ;
    USE SIGNAL ;
    PORT
      LAYER met3 ;
        RECT 418.560 149.050 419.560 149.330 ;
    END
  END dout[230]

  PIN dout[231]
    DIRECTION OUTPUT ;
    USE SIGNAL ;
    PORT
      LAYER met3 ;
        RECT 418.560 149.685 419.560 149.965 ;
    END
  END dout[231]

  PIN dout[232]
    DIRECTION OUTPUT ;
    USE SIGNAL ;
    PORT
      LAYER met3 ;
        RECT 418.560 150.320 419.560 150.600 ;
    END
  END dout[232]

  PIN dout[233]
    DIRECTION OUTPUT ;
    USE SIGNAL ;
    PORT
      LAYER met3 ;
        RECT 418.560 150.955 419.560 151.235 ;
    END
  END dout[233]

  PIN dout[234]
    DIRECTION OUTPUT ;
    USE SIGNAL ;
    PORT
      LAYER met3 ;
        RECT 418.560 151.590 419.560 151.870 ;
    END
  END dout[234]

  PIN dout[235]
    DIRECTION OUTPUT ;
    USE SIGNAL ;
    PORT
      LAYER met3 ;
        RECT 418.560 152.225 419.560 152.505 ;
    END
  END dout[235]

  PIN dout[236]
    DIRECTION OUTPUT ;
    USE SIGNAL ;
    PORT
      LAYER met3 ;
        RECT 418.560 152.860 419.560 153.140 ;
    END
  END dout[236]

  PIN dout[237]
    DIRECTION OUTPUT ;
    USE SIGNAL ;
    PORT
      LAYER met3 ;
        RECT 418.560 153.495 419.560 153.775 ;
    END
  END dout[237]

  PIN dout[238]
    DIRECTION OUTPUT ;
    USE SIGNAL ;
    PORT
      LAYER met3 ;
        RECT 418.560 154.130 419.560 154.410 ;
    END
  END dout[238]

  PIN dout[239]
    DIRECTION OUTPUT ;
    USE SIGNAL ;
    PORT
      LAYER met3 ;
        RECT 418.560 154.765 419.560 155.045 ;
    END
  END dout[239]

  PIN dout[240]
    DIRECTION OUTPUT ;
    USE SIGNAL ;
    PORT
      LAYER met3 ;
        RECT 418.560 155.400 419.560 155.680 ;
    END
  END dout[240]

  PIN dout[241]
    DIRECTION OUTPUT ;
    USE SIGNAL ;
    PORT
      LAYER met3 ;
        RECT 418.560 156.035 419.560 156.315 ;
    END
  END dout[241]

  PIN dout[242]
    DIRECTION OUTPUT ;
    USE SIGNAL ;
    PORT
      LAYER met3 ;
        RECT 418.560 156.670 419.560 156.950 ;
    END
  END dout[242]

  PIN dout[243]
    DIRECTION OUTPUT ;
    USE SIGNAL ;
    PORT
      LAYER met3 ;
        RECT 418.560 157.305 419.560 157.585 ;
    END
  END dout[243]

  PIN dout[244]
    DIRECTION OUTPUT ;
    USE SIGNAL ;
    PORT
      LAYER met3 ;
        RECT 418.560 157.940 419.560 158.220 ;
    END
  END dout[244]

  PIN dout[245]
    DIRECTION OUTPUT ;
    USE SIGNAL ;
    PORT
      LAYER met3 ;
        RECT 418.560 158.575 419.560 158.855 ;
    END
  END dout[245]

  PIN dout[246]
    DIRECTION OUTPUT ;
    USE SIGNAL ;
    PORT
      LAYER met3 ;
        RECT 418.560 159.210 419.560 159.490 ;
    END
  END dout[246]

  PIN dout[247]
    DIRECTION OUTPUT ;
    USE SIGNAL ;
    PORT
      LAYER met3 ;
        RECT 418.560 159.845 419.560 160.125 ;
    END
  END dout[247]

  PIN dout[248]
    DIRECTION OUTPUT ;
    USE SIGNAL ;
    PORT
      LAYER met3 ;
        RECT 418.560 160.480 419.560 160.760 ;
    END
  END dout[248]

  PIN dout[249]
    DIRECTION OUTPUT ;
    USE SIGNAL ;
    PORT
      LAYER met3 ;
        RECT 418.560 161.115 419.560 161.395 ;
    END
  END dout[249]

  PIN dout[250]
    DIRECTION OUTPUT ;
    USE SIGNAL ;
    PORT
      LAYER met3 ;
        RECT 418.560 161.750 419.560 162.030 ;
    END
  END dout[250]

  PIN dout[251]
    DIRECTION OUTPUT ;
    USE SIGNAL ;
    PORT
      LAYER met3 ;
        RECT 418.560 162.385 419.560 162.665 ;
    END
  END dout[251]

  PIN dout[252]
    DIRECTION OUTPUT ;
    USE SIGNAL ;
    PORT
      LAYER met3 ;
        RECT 418.560 163.020 419.560 163.300 ;
    END
  END dout[252]

  PIN dout[253]
    DIRECTION OUTPUT ;
    USE SIGNAL ;
    PORT
      LAYER met3 ;
        RECT 418.560 163.655 419.560 163.935 ;
    END
  END dout[253]

  PIN dout[254]
    DIRECTION OUTPUT ;
    USE SIGNAL ;
    PORT
      LAYER met3 ;
        RECT 418.560 164.290 419.560 164.570 ;
    END
  END dout[254]

  PIN dout[255]
    DIRECTION OUTPUT ;
    USE SIGNAL ;
    PORT
      LAYER met3 ;
        RECT 418.560 164.925 419.560 165.205 ;
    END
  END dout[255]

  PIN dout[256]
    DIRECTION OUTPUT ;
    USE SIGNAL ;
    PORT
      LAYER met3 ;
        RECT 418.560 165.560 419.560 165.840 ;
    END
  END dout[256]

  PIN dout[257]
    DIRECTION OUTPUT ;
    USE SIGNAL ;
    PORT
      LAYER met3 ;
        RECT 418.560 166.195 419.560 166.475 ;
    END
  END dout[257]

  PIN dout[258]
    DIRECTION OUTPUT ;
    USE SIGNAL ;
    PORT
      LAYER met3 ;
        RECT 418.560 166.830 419.560 167.110 ;
    END
  END dout[258]

  PIN dout[259]
    DIRECTION OUTPUT ;
    USE SIGNAL ;
    PORT
      LAYER met3 ;
        RECT 418.560 167.465 419.560 167.745 ;
    END
  END dout[259]

  PIN dout[260]
    DIRECTION OUTPUT ;
    USE SIGNAL ;
    PORT
      LAYER met3 ;
        RECT 418.560 168.100 419.560 168.380 ;
    END
  END dout[260]

  PIN dout[261]
    DIRECTION OUTPUT ;
    USE SIGNAL ;
    PORT
      LAYER met3 ;
        RECT 418.560 168.735 419.560 169.015 ;
    END
  END dout[261]

  PIN dout[262]
    DIRECTION OUTPUT ;
    USE SIGNAL ;
    PORT
      LAYER met3 ;
        RECT 418.560 169.370 419.560 169.650 ;
    END
  END dout[262]

  PIN dout[263]
    DIRECTION OUTPUT ;
    USE SIGNAL ;
    PORT
      LAYER met3 ;
        RECT 418.560 170.005 419.560 170.285 ;
    END
  END dout[263]

  PIN dout[264]
    DIRECTION OUTPUT ;
    USE SIGNAL ;
    PORT
      LAYER met3 ;
        RECT 418.560 170.640 419.560 170.920 ;
    END
  END dout[264]

  PIN dout[265]
    DIRECTION OUTPUT ;
    USE SIGNAL ;
    PORT
      LAYER met3 ;
        RECT 418.560 171.275 419.560 171.555 ;
    END
  END dout[265]

  PIN dout[266]
    DIRECTION OUTPUT ;
    USE SIGNAL ;
    PORT
      LAYER met3 ;
        RECT 418.560 171.910 419.560 172.190 ;
    END
  END dout[266]

  PIN dout[267]
    DIRECTION OUTPUT ;
    USE SIGNAL ;
    PORT
      LAYER met3 ;
        RECT 418.560 172.545 419.560 172.825 ;
    END
  END dout[267]

  PIN dout[268]
    DIRECTION OUTPUT ;
    USE SIGNAL ;
    PORT
      LAYER met3 ;
        RECT 418.560 173.180 419.560 173.460 ;
    END
  END dout[268]

  PIN dout[269]
    DIRECTION OUTPUT ;
    USE SIGNAL ;
    PORT
      LAYER met3 ;
        RECT 418.560 173.815 419.560 174.095 ;
    END
  END dout[269]

  PIN dout[270]
    DIRECTION OUTPUT ;
    USE SIGNAL ;
    PORT
      LAYER met3 ;
        RECT 418.560 174.450 419.560 174.730 ;
    END
  END dout[270]

  PIN dout[271]
    DIRECTION OUTPUT ;
    USE SIGNAL ;
    PORT
      LAYER met3 ;
        RECT 418.560 175.085 419.560 175.365 ;
    END
  END dout[271]

  PIN dout[272]
    DIRECTION OUTPUT ;
    USE SIGNAL ;
    PORT
      LAYER met3 ;
        RECT 418.560 175.720 419.560 176.000 ;
    END
  END dout[272]

  PIN dout[273]
    DIRECTION OUTPUT ;
    USE SIGNAL ;
    PORT
      LAYER met3 ;
        RECT 418.560 176.355 419.560 176.635 ;
    END
  END dout[273]

  PIN dout[274]
    DIRECTION OUTPUT ;
    USE SIGNAL ;
    PORT
      LAYER met3 ;
        RECT 418.560 176.990 419.560 177.270 ;
    END
  END dout[274]

  PIN dout[275]
    DIRECTION OUTPUT ;
    USE SIGNAL ;
    PORT
      LAYER met3 ;
        RECT 418.560 177.625 419.560 177.905 ;
    END
  END dout[275]

  PIN dout[276]
    DIRECTION OUTPUT ;
    USE SIGNAL ;
    PORT
      LAYER met3 ;
        RECT 418.560 178.260 419.560 178.540 ;
    END
  END dout[276]

  PIN dout[277]
    DIRECTION OUTPUT ;
    USE SIGNAL ;
    PORT
      LAYER met3 ;
        RECT 418.560 178.895 419.560 179.175 ;
    END
  END dout[277]

  PIN dout[278]
    DIRECTION OUTPUT ;
    USE SIGNAL ;
    PORT
      LAYER met3 ;
        RECT 418.560 179.530 419.560 179.810 ;
    END
  END dout[278]

  PIN dout[279]
    DIRECTION OUTPUT ;
    USE SIGNAL ;
    PORT
      LAYER met3 ;
        RECT 418.560 180.165 419.560 180.445 ;
    END
  END dout[279]

  PIN dout[280]
    DIRECTION OUTPUT ;
    USE SIGNAL ;
    PORT
      LAYER met3 ;
        RECT 418.560 180.800 419.560 181.080 ;
    END
  END dout[280]

  PIN dout[281]
    DIRECTION OUTPUT ;
    USE SIGNAL ;
    PORT
      LAYER met3 ;
        RECT 418.560 181.435 419.560 181.715 ;
    END
  END dout[281]

  PIN dout[282]
    DIRECTION OUTPUT ;
    USE SIGNAL ;
    PORT
      LAYER met3 ;
        RECT 418.560 182.070 419.560 182.350 ;
    END
  END dout[282]

  PIN dout[283]
    DIRECTION OUTPUT ;
    USE SIGNAL ;
    PORT
      LAYER met3 ;
        RECT 418.560 182.705 419.560 182.985 ;
    END
  END dout[283]

  PIN dout[284]
    DIRECTION OUTPUT ;
    USE SIGNAL ;
    PORT
      LAYER met3 ;
        RECT 418.560 183.340 419.560 183.620 ;
    END
  END dout[284]

  PIN dout[285]
    DIRECTION OUTPUT ;
    USE SIGNAL ;
    PORT
      LAYER met3 ;
        RECT 418.560 183.975 419.560 184.255 ;
    END
  END dout[285]

  PIN dout[286]
    DIRECTION OUTPUT ;
    USE SIGNAL ;
    PORT
      LAYER met3 ;
        RECT 418.560 184.610 419.560 184.890 ;
    END
  END dout[286]

  PIN dout[287]
    DIRECTION OUTPUT ;
    USE SIGNAL ;
    PORT
      LAYER met3 ;
        RECT 418.560 185.245 419.560 185.525 ;
    END
  END dout[287]

  PIN dout[288]
    DIRECTION OUTPUT ;
    USE SIGNAL ;
    PORT
      LAYER met3 ;
        RECT 418.560 185.880 419.560 186.160 ;
    END
  END dout[288]

  PIN dout[289]
    DIRECTION OUTPUT ;
    USE SIGNAL ;
    PORT
      LAYER met3 ;
        RECT 418.560 186.515 419.560 186.795 ;
    END
  END dout[289]

  PIN dout[290]
    DIRECTION OUTPUT ;
    USE SIGNAL ;
    PORT
      LAYER met3 ;
        RECT 418.560 187.150 419.560 187.430 ;
    END
  END dout[290]

  PIN dout[291]
    DIRECTION OUTPUT ;
    USE SIGNAL ;
    PORT
      LAYER met3 ;
        RECT 418.560 187.785 419.560 188.065 ;
    END
  END dout[291]

  PIN dout[292]
    DIRECTION OUTPUT ;
    USE SIGNAL ;
    PORT
      LAYER met3 ;
        RECT 418.560 188.420 419.560 188.700 ;
    END
  END dout[292]

  PIN dout[293]
    DIRECTION OUTPUT ;
    USE SIGNAL ;
    PORT
      LAYER met3 ;
        RECT 418.560 189.055 419.560 189.335 ;
    END
  END dout[293]

  PIN dout[294]
    DIRECTION OUTPUT ;
    USE SIGNAL ;
    PORT
      LAYER met3 ;
        RECT 418.560 189.690 419.560 189.970 ;
    END
  END dout[294]

  PIN dout[295]
    DIRECTION OUTPUT ;
    USE SIGNAL ;
    PORT
      LAYER met3 ;
        RECT 418.560 190.325 419.560 190.605 ;
    END
  END dout[295]

  PIN dout[296]
    DIRECTION OUTPUT ;
    USE SIGNAL ;
    PORT
      LAYER met3 ;
        RECT 418.560 190.960 419.560 191.240 ;
    END
  END dout[296]

  PIN dout[297]
    DIRECTION OUTPUT ;
    USE SIGNAL ;
    PORT
      LAYER met3 ;
        RECT 418.560 191.595 419.560 191.875 ;
    END
  END dout[297]

  PIN dout[298]
    DIRECTION OUTPUT ;
    USE SIGNAL ;
    PORT
      LAYER met3 ;
        RECT 418.560 192.230 419.560 192.510 ;
    END
  END dout[298]

  PIN dout[299]
    DIRECTION OUTPUT ;
    USE SIGNAL ;
    PORT
      LAYER met3 ;
        RECT 418.560 192.865 419.560 193.145 ;
    END
  END dout[299]

  PIN dout[300]
    DIRECTION OUTPUT ;
    USE SIGNAL ;
    PORT
      LAYER met3 ;
        RECT 418.560 193.500 419.560 193.780 ;
    END
  END dout[300]

  PIN dout[301]
    DIRECTION OUTPUT ;
    USE SIGNAL ;
    PORT
      LAYER met3 ;
        RECT 418.560 194.135 419.560 194.415 ;
    END
  END dout[301]

  PIN dout[302]
    DIRECTION OUTPUT ;
    USE SIGNAL ;
    PORT
      LAYER met3 ;
        RECT 418.560 194.770 419.560 195.050 ;
    END
  END dout[302]

  PIN dout[303]
    DIRECTION OUTPUT ;
    USE SIGNAL ;
    PORT
      LAYER met3 ;
        RECT 418.560 195.405 419.560 195.685 ;
    END
  END dout[303]

  PIN dout[304]
    DIRECTION OUTPUT ;
    USE SIGNAL ;
    PORT
      LAYER met3 ;
        RECT 418.560 196.040 419.560 196.320 ;
    END
  END dout[304]

  PIN dout[305]
    DIRECTION OUTPUT ;
    USE SIGNAL ;
    PORT
      LAYER met3 ;
        RECT 418.560 196.675 419.560 196.955 ;
    END
  END dout[305]

  PIN dout[306]
    DIRECTION OUTPUT ;
    USE SIGNAL ;
    PORT
      LAYER met3 ;
        RECT 418.560 197.310 419.560 197.590 ;
    END
  END dout[306]

  PIN dout[307]
    DIRECTION OUTPUT ;
    USE SIGNAL ;
    PORT
      LAYER met3 ;
        RECT 418.560 197.945 419.560 198.225 ;
    END
  END dout[307]

  PIN dout[308]
    DIRECTION OUTPUT ;
    USE SIGNAL ;
    PORT
      LAYER met3 ;
        RECT 418.560 198.580 419.560 198.860 ;
    END
  END dout[308]

  PIN dout[309]
    DIRECTION OUTPUT ;
    USE SIGNAL ;
    PORT
      LAYER met3 ;
        RECT 418.560 199.215 419.560 199.495 ;
    END
  END dout[309]

  PIN dout[310]
    DIRECTION OUTPUT ;
    USE SIGNAL ;
    PORT
      LAYER met3 ;
        RECT 418.560 199.850 419.560 200.130 ;
    END
  END dout[310]

  PIN dout[311]
    DIRECTION OUTPUT ;
    USE SIGNAL ;
    PORT
      LAYER met3 ;
        RECT 418.560 200.485 419.560 200.765 ;
    END
  END dout[311]

  PIN dout[312]
    DIRECTION OUTPUT ;
    USE SIGNAL ;
    PORT
      LAYER met3 ;
        RECT 418.560 201.120 419.560 201.400 ;
    END
  END dout[312]

  PIN dout[313]
    DIRECTION OUTPUT ;
    USE SIGNAL ;
    PORT
      LAYER met3 ;
        RECT 418.560 201.755 419.560 202.035 ;
    END
  END dout[313]

  PIN dout[314]
    DIRECTION OUTPUT ;
    USE SIGNAL ;
    PORT
      LAYER met3 ;
        RECT 418.560 202.390 419.560 202.670 ;
    END
  END dout[314]

  PIN dout[315]
    DIRECTION OUTPUT ;
    USE SIGNAL ;
    PORT
      LAYER met3 ;
        RECT 418.560 203.025 419.560 203.305 ;
    END
  END dout[315]

  PIN dout[316]
    DIRECTION OUTPUT ;
    USE SIGNAL ;
    PORT
      LAYER met3 ;
        RECT 418.560 203.660 419.560 203.940 ;
    END
  END dout[316]

  PIN dout[317]
    DIRECTION OUTPUT ;
    USE SIGNAL ;
    PORT
      LAYER met3 ;
        RECT 418.560 204.295 419.560 204.575 ;
    END
  END dout[317]

  PIN dout[318]
    DIRECTION OUTPUT ;
    USE SIGNAL ;
    PORT
      LAYER met3 ;
        RECT 418.560 204.930 419.560 205.210 ;
    END
  END dout[318]

  PIN dout[319]
    DIRECTION OUTPUT ;
    USE SIGNAL ;
    PORT
      LAYER met3 ;
        RECT 418.560 205.565 419.560 205.845 ;
    END
  END dout[319]

  PIN dout[320]
    DIRECTION OUTPUT ;
    USE SIGNAL ;
    PORT
      LAYER met3 ;
        RECT 418.560 206.200 419.560 206.480 ;
    END
  END dout[320]

  PIN dout[321]
    DIRECTION OUTPUT ;
    USE SIGNAL ;
    PORT
      LAYER met3 ;
        RECT 418.560 206.835 419.560 207.115 ;
    END
  END dout[321]

  PIN dout[322]
    DIRECTION OUTPUT ;
    USE SIGNAL ;
    PORT
      LAYER met3 ;
        RECT 418.560 207.470 419.560 207.750 ;
    END
  END dout[322]

  PIN dout[323]
    DIRECTION OUTPUT ;
    USE SIGNAL ;
    PORT
      LAYER met3 ;
        RECT 418.560 208.105 419.560 208.385 ;
    END
  END dout[323]

  PIN dout[324]
    DIRECTION OUTPUT ;
    USE SIGNAL ;
    PORT
      LAYER met3 ;
        RECT 418.560 208.740 419.560 209.020 ;
    END
  END dout[324]

  PIN dout[325]
    DIRECTION OUTPUT ;
    USE SIGNAL ;
    PORT
      LAYER met3 ;
        RECT 418.560 209.375 419.560 209.655 ;
    END
  END dout[325]

  PIN dout[326]
    DIRECTION OUTPUT ;
    USE SIGNAL ;
    PORT
      LAYER met3 ;
        RECT 418.560 210.010 419.560 210.290 ;
    END
  END dout[326]

  PIN dout[327]
    DIRECTION OUTPUT ;
    USE SIGNAL ;
    PORT
      LAYER met3 ;
        RECT 418.560 210.645 419.560 210.925 ;
    END
  END dout[327]

  PIN dout[328]
    DIRECTION OUTPUT ;
    USE SIGNAL ;
    PORT
      LAYER met3 ;
        RECT 418.560 211.280 419.560 211.560 ;
    END
  END dout[328]

  PIN dout[329]
    DIRECTION OUTPUT ;
    USE SIGNAL ;
    PORT
      LAYER met3 ;
        RECT 418.560 211.915 419.560 212.195 ;
    END
  END dout[329]

  PIN dout[330]
    DIRECTION OUTPUT ;
    USE SIGNAL ;
    PORT
      LAYER met3 ;
        RECT 418.560 212.550 419.560 212.830 ;
    END
  END dout[330]

  PIN dout[331]
    DIRECTION OUTPUT ;
    USE SIGNAL ;
    PORT
      LAYER met3 ;
        RECT 418.560 213.185 419.560 213.465 ;
    END
  END dout[331]

  PIN dout[332]
    DIRECTION OUTPUT ;
    USE SIGNAL ;
    PORT
      LAYER met3 ;
        RECT 418.560 213.820 419.560 214.100 ;
    END
  END dout[332]

  PIN dout[333]
    DIRECTION OUTPUT ;
    USE SIGNAL ;
    PORT
      LAYER met3 ;
        RECT 418.560 214.455 419.560 214.735 ;
    END
  END dout[333]

  PIN dout[334]
    DIRECTION OUTPUT ;
    USE SIGNAL ;
    PORT
      LAYER met3 ;
        RECT 418.560 215.090 419.560 215.370 ;
    END
  END dout[334]

  PIN dout[335]
    DIRECTION OUTPUT ;
    USE SIGNAL ;
    PORT
      LAYER met3 ;
        RECT 418.560 215.725 419.560 216.005 ;
    END
  END dout[335]

  PIN dout[336]
    DIRECTION OUTPUT ;
    USE SIGNAL ;
    PORT
      LAYER met3 ;
        RECT 418.560 216.360 419.560 216.640 ;
    END
  END dout[336]

  PIN dout[337]
    DIRECTION OUTPUT ;
    USE SIGNAL ;
    PORT
      LAYER met3 ;
        RECT 418.560 216.995 419.560 217.275 ;
    END
  END dout[337]

  PIN dout[338]
    DIRECTION OUTPUT ;
    USE SIGNAL ;
    PORT
      LAYER met3 ;
        RECT 418.560 217.630 419.560 217.910 ;
    END
  END dout[338]

  PIN dout[339]
    DIRECTION OUTPUT ;
    USE SIGNAL ;
    PORT
      LAYER met3 ;
        RECT 418.560 218.265 419.560 218.545 ;
    END
  END dout[339]

  PIN dout[340]
    DIRECTION OUTPUT ;
    USE SIGNAL ;
    PORT
      LAYER met3 ;
        RECT 418.560 218.900 419.560 219.180 ;
    END
  END dout[340]

  PIN dout[341]
    DIRECTION OUTPUT ;
    USE SIGNAL ;
    PORT
      LAYER met3 ;
        RECT 418.560 219.535 419.560 219.815 ;
    END
  END dout[341]

  PIN dout[342]
    DIRECTION OUTPUT ;
    USE SIGNAL ;
    PORT
      LAYER met3 ;
        RECT 418.560 220.170 419.560 220.450 ;
    END
  END dout[342]

  PIN dout[343]
    DIRECTION OUTPUT ;
    USE SIGNAL ;
    PORT
      LAYER met3 ;
        RECT 418.560 220.805 419.560 221.085 ;
    END
  END dout[343]

  PIN dout[344]
    DIRECTION OUTPUT ;
    USE SIGNAL ;
    PORT
      LAYER met3 ;
        RECT 418.560 221.440 419.560 221.720 ;
    END
  END dout[344]

  PIN dout[345]
    DIRECTION OUTPUT ;
    USE SIGNAL ;
    PORT
      LAYER met3 ;
        RECT 418.560 222.075 419.560 222.355 ;
    END
  END dout[345]

  PIN dout[346]
    DIRECTION OUTPUT ;
    USE SIGNAL ;
    PORT
      LAYER met3 ;
        RECT 418.560 222.710 419.560 222.990 ;
    END
  END dout[346]

  PIN dout[347]
    DIRECTION OUTPUT ;
    USE SIGNAL ;
    PORT
      LAYER met3 ;
        RECT 418.560 223.345 419.560 223.625 ;
    END
  END dout[347]

  PIN dout[348]
    DIRECTION OUTPUT ;
    USE SIGNAL ;
    PORT
      LAYER met3 ;
        RECT 418.560 223.980 419.560 224.260 ;
    END
  END dout[348]

  PIN dout[349]
    DIRECTION OUTPUT ;
    USE SIGNAL ;
    PORT
      LAYER met3 ;
        RECT 418.560 224.615 419.560 224.895 ;
    END
  END dout[349]

  PIN dout[350]
    DIRECTION OUTPUT ;
    USE SIGNAL ;
    PORT
      LAYER met3 ;
        RECT 418.560 225.250 419.560 225.530 ;
    END
  END dout[350]

  PIN dout[351]
    DIRECTION OUTPUT ;
    USE SIGNAL ;
    PORT
      LAYER met3 ;
        RECT 418.560 225.885 419.560 226.165 ;
    END
  END dout[351]

  PIN dout[352]
    DIRECTION OUTPUT ;
    USE SIGNAL ;
    PORT
      LAYER met3 ;
        RECT 418.560 226.520 419.560 226.800 ;
    END
  END dout[352]

  PIN dout[353]
    DIRECTION OUTPUT ;
    USE SIGNAL ;
    PORT
      LAYER met3 ;
        RECT 418.560 227.155 419.560 227.435 ;
    END
  END dout[353]

  PIN dout[354]
    DIRECTION OUTPUT ;
    USE SIGNAL ;
    PORT
      LAYER met3 ;
        RECT 418.560 227.790 419.560 228.070 ;
    END
  END dout[354]

  PIN dout[355]
    DIRECTION OUTPUT ;
    USE SIGNAL ;
    PORT
      LAYER met3 ;
        RECT 418.560 228.425 419.560 228.705 ;
    END
  END dout[355]

  PIN dout[356]
    DIRECTION OUTPUT ;
    USE SIGNAL ;
    PORT
      LAYER met3 ;
        RECT 418.560 229.060 419.560 229.340 ;
    END
  END dout[356]

  PIN dout[357]
    DIRECTION OUTPUT ;
    USE SIGNAL ;
    PORT
      LAYER met3 ;
        RECT 418.560 229.695 419.560 229.975 ;
    END
  END dout[357]

  PIN dout[358]
    DIRECTION OUTPUT ;
    USE SIGNAL ;
    PORT
      LAYER met3 ;
        RECT 418.560 230.330 419.560 230.610 ;
    END
  END dout[358]

  PIN dout[359]
    DIRECTION OUTPUT ;
    USE SIGNAL ;
    PORT
      LAYER met3 ;
        RECT 418.560 230.965 419.560 231.245 ;
    END
  END dout[359]

  PIN dout[360]
    DIRECTION OUTPUT ;
    USE SIGNAL ;
    PORT
      LAYER met3 ;
        RECT 418.560 231.600 419.560 231.880 ;
    END
  END dout[360]

  PIN dout[361]
    DIRECTION OUTPUT ;
    USE SIGNAL ;
    PORT
      LAYER met3 ;
        RECT 418.560 232.235 419.560 232.515 ;
    END
  END dout[361]

  PIN dout[362]
    DIRECTION OUTPUT ;
    USE SIGNAL ;
    PORT
      LAYER met3 ;
        RECT 418.560 232.870 419.560 233.150 ;
    END
  END dout[362]

  PIN dout[363]
    DIRECTION OUTPUT ;
    USE SIGNAL ;
    PORT
      LAYER met3 ;
        RECT 418.560 233.505 419.560 233.785 ;
    END
  END dout[363]

  PIN dout[364]
    DIRECTION OUTPUT ;
    USE SIGNAL ;
    PORT
      LAYER met3 ;
        RECT 418.560 234.140 419.560 234.420 ;
    END
  END dout[364]

  PIN dout[365]
    DIRECTION OUTPUT ;
    USE SIGNAL ;
    PORT
      LAYER met3 ;
        RECT 418.560 234.775 419.560 235.055 ;
    END
  END dout[365]

  PIN dout[366]
    DIRECTION OUTPUT ;
    USE SIGNAL ;
    PORT
      LAYER met3 ;
        RECT 418.560 235.410 419.560 235.690 ;
    END
  END dout[366]

  PIN dout[367]
    DIRECTION OUTPUT ;
    USE SIGNAL ;
    PORT
      LAYER met3 ;
        RECT 418.560 236.045 419.560 236.325 ;
    END
  END dout[367]

  PIN dout[368]
    DIRECTION OUTPUT ;
    USE SIGNAL ;
    PORT
      LAYER met3 ;
        RECT 418.560 236.680 419.560 236.960 ;
    END
  END dout[368]

  PIN dout[369]
    DIRECTION OUTPUT ;
    USE SIGNAL ;
    PORT
      LAYER met3 ;
        RECT 418.560 237.315 419.560 237.595 ;
    END
  END dout[369]

  PIN dout[370]
    DIRECTION OUTPUT ;
    USE SIGNAL ;
    PORT
      LAYER met3 ;
        RECT 418.560 237.950 419.560 238.230 ;
    END
  END dout[370]

  PIN dout[371]
    DIRECTION OUTPUT ;
    USE SIGNAL ;
    PORT
      LAYER met3 ;
        RECT 418.560 238.585 419.560 238.865 ;
    END
  END dout[371]

  PIN dout[372]
    DIRECTION OUTPUT ;
    USE SIGNAL ;
    PORT
      LAYER met3 ;
        RECT 418.560 239.220 419.560 239.500 ;
    END
  END dout[372]

  PIN dout[373]
    DIRECTION OUTPUT ;
    USE SIGNAL ;
    PORT
      LAYER met3 ;
        RECT 418.560 239.855 419.560 240.135 ;
    END
  END dout[373]

  PIN dout[374]
    DIRECTION OUTPUT ;
    USE SIGNAL ;
    PORT
      LAYER met3 ;
        RECT 418.560 240.490 419.560 240.770 ;
    END
  END dout[374]

  PIN dout[375]
    DIRECTION OUTPUT ;
    USE SIGNAL ;
    PORT
      LAYER met3 ;
        RECT 418.560 241.125 419.560 241.405 ;
    END
  END dout[375]

  PIN dout[376]
    DIRECTION OUTPUT ;
    USE SIGNAL ;
    PORT
      LAYER met3 ;
        RECT 418.560 241.760 419.560 242.040 ;
    END
  END dout[376]

  PIN dout[377]
    DIRECTION OUTPUT ;
    USE SIGNAL ;
    PORT
      LAYER met3 ;
        RECT 418.560 242.395 419.560 242.675 ;
    END
  END dout[377]

  PIN dout[378]
    DIRECTION OUTPUT ;
    USE SIGNAL ;
    PORT
      LAYER met3 ;
        RECT 418.560 243.030 419.560 243.310 ;
    END
  END dout[378]

  PIN dout[379]
    DIRECTION OUTPUT ;
    USE SIGNAL ;
    PORT
      LAYER met3 ;
        RECT 418.560 243.665 419.560 243.945 ;
    END
  END dout[379]

  PIN dout[380]
    DIRECTION OUTPUT ;
    USE SIGNAL ;
    PORT
      LAYER met3 ;
        RECT 418.560 244.300 419.560 244.580 ;
    END
  END dout[380]

  PIN dout[381]
    DIRECTION OUTPUT ;
    USE SIGNAL ;
    PORT
      LAYER met3 ;
        RECT 418.560 244.935 419.560 245.215 ;
    END
  END dout[381]

  PIN dout[382]
    DIRECTION OUTPUT ;
    USE SIGNAL ;
    PORT
      LAYER met3 ;
        RECT 418.560 245.570 419.560 245.850 ;
    END
  END dout[382]

  PIN dout[383]
    DIRECTION OUTPUT ;
    USE SIGNAL ;
    PORT
      LAYER met3 ;
        RECT 418.560 246.205 419.560 246.485 ;
    END
  END dout[383]

  PIN dout[384]
    DIRECTION OUTPUT ;
    USE SIGNAL ;
    PORT
      LAYER met3 ;
        RECT 418.560 246.840 419.560 247.120 ;
    END
  END dout[384]

  PIN dout[385]
    DIRECTION OUTPUT ;
    USE SIGNAL ;
    PORT
      LAYER met3 ;
        RECT 418.560 247.475 419.560 247.755 ;
    END
  END dout[385]

  PIN dout[386]
    DIRECTION OUTPUT ;
    USE SIGNAL ;
    PORT
      LAYER met3 ;
        RECT 418.560 248.110 419.560 248.390 ;
    END
  END dout[386]

  PIN dout[387]
    DIRECTION OUTPUT ;
    USE SIGNAL ;
    PORT
      LAYER met3 ;
        RECT 418.560 248.745 419.560 249.025 ;
    END
  END dout[387]

  PIN dout[388]
    DIRECTION OUTPUT ;
    USE SIGNAL ;
    PORT
      LAYER met3 ;
        RECT 418.560 249.380 419.560 249.660 ;
    END
  END dout[388]

  PIN dout[389]
    DIRECTION OUTPUT ;
    USE SIGNAL ;
    PORT
      LAYER met3 ;
        RECT 418.560 250.015 419.560 250.295 ;
    END
  END dout[389]

  PIN dout[390]
    DIRECTION OUTPUT ;
    USE SIGNAL ;
    PORT
      LAYER met3 ;
        RECT 418.560 250.650 419.560 250.930 ;
    END
  END dout[390]

  PIN dout[391]
    DIRECTION OUTPUT ;
    USE SIGNAL ;
    PORT
      LAYER met3 ;
        RECT 418.560 251.285 419.560 251.565 ;
    END
  END dout[391]

  PIN dout[392]
    DIRECTION OUTPUT ;
    USE SIGNAL ;
    PORT
      LAYER met3 ;
        RECT 418.560 251.920 419.560 252.200 ;
    END
  END dout[392]

  PIN dout[393]
    DIRECTION OUTPUT ;
    USE SIGNAL ;
    PORT
      LAYER met3 ;
        RECT 418.560 252.555 419.560 252.835 ;
    END
  END dout[393]

  PIN dout[394]
    DIRECTION OUTPUT ;
    USE SIGNAL ;
    PORT
      LAYER met3 ;
        RECT 418.560 253.190 419.560 253.470 ;
    END
  END dout[394]

  PIN dout[395]
    DIRECTION OUTPUT ;
    USE SIGNAL ;
    PORT
      LAYER met3 ;
        RECT 418.560 253.825 419.560 254.105 ;
    END
  END dout[395]

  PIN dout[396]
    DIRECTION OUTPUT ;
    USE SIGNAL ;
    PORT
      LAYER met3 ;
        RECT 418.560 254.460 419.560 254.740 ;
    END
  END dout[396]

  PIN dout[397]
    DIRECTION OUTPUT ;
    USE SIGNAL ;
    PORT
      LAYER met3 ;
        RECT 418.560 255.095 419.560 255.375 ;
    END
  END dout[397]

  PIN dout[398]
    DIRECTION OUTPUT ;
    USE SIGNAL ;
    PORT
      LAYER met3 ;
        RECT 418.560 255.730 419.560 256.010 ;
    END
  END dout[398]

  PIN dout[399]
    DIRECTION OUTPUT ;
    USE SIGNAL ;
    PORT
      LAYER met3 ;
        RECT 418.560 256.365 419.560 256.645 ;
    END
  END dout[399]

  PIN dout[400]
    DIRECTION OUTPUT ;
    USE SIGNAL ;
    PORT
      LAYER met3 ;
        RECT 418.560 257.000 419.560 257.280 ;
    END
  END dout[400]

  PIN dout[401]
    DIRECTION OUTPUT ;
    USE SIGNAL ;
    PORT
      LAYER met3 ;
        RECT 418.560 257.635 419.560 257.915 ;
    END
  END dout[401]

  PIN dout[402]
    DIRECTION OUTPUT ;
    USE SIGNAL ;
    PORT
      LAYER met3 ;
        RECT 418.560 258.270 419.560 258.550 ;
    END
  END dout[402]

  PIN dout[403]
    DIRECTION OUTPUT ;
    USE SIGNAL ;
    PORT
      LAYER met3 ;
        RECT 418.560 258.905 419.560 259.185 ;
    END
  END dout[403]

  PIN dout[404]
    DIRECTION OUTPUT ;
    USE SIGNAL ;
    PORT
      LAYER met3 ;
        RECT 418.560 259.540 419.560 259.820 ;
    END
  END dout[404]

  PIN dout[405]
    DIRECTION OUTPUT ;
    USE SIGNAL ;
    PORT
      LAYER met3 ;
        RECT 418.560 260.175 419.560 260.455 ;
    END
  END dout[405]

  PIN dout[406]
    DIRECTION OUTPUT ;
    USE SIGNAL ;
    PORT
      LAYER met3 ;
        RECT 418.560 260.810 419.560 261.090 ;
    END
  END dout[406]

  PIN dout[407]
    DIRECTION OUTPUT ;
    USE SIGNAL ;
    PORT
      LAYER met3 ;
        RECT 418.560 261.445 419.560 261.725 ;
    END
  END dout[407]

  PIN dout[408]
    DIRECTION OUTPUT ;
    USE SIGNAL ;
    PORT
      LAYER met3 ;
        RECT 418.560 262.080 419.560 262.360 ;
    END
  END dout[408]

  PIN dout[409]
    DIRECTION OUTPUT ;
    USE SIGNAL ;
    PORT
      LAYER met3 ;
        RECT 418.560 262.715 419.560 262.995 ;
    END
  END dout[409]

  PIN dout[410]
    DIRECTION OUTPUT ;
    USE SIGNAL ;
    PORT
      LAYER met3 ;
        RECT 418.560 263.350 419.560 263.630 ;
    END
  END dout[410]

  PIN dout[411]
    DIRECTION OUTPUT ;
    USE SIGNAL ;
    PORT
      LAYER met3 ;
        RECT 418.560 263.985 419.560 264.265 ;
    END
  END dout[411]

  PIN dout[412]
    DIRECTION OUTPUT ;
    USE SIGNAL ;
    PORT
      LAYER met3 ;
        RECT 418.560 264.620 419.560 264.900 ;
    END
  END dout[412]

  PIN dout[413]
    DIRECTION OUTPUT ;
    USE SIGNAL ;
    PORT
      LAYER met3 ;
        RECT 418.560 265.255 419.560 265.535 ;
    END
  END dout[413]

  PIN dout[414]
    DIRECTION OUTPUT ;
    USE SIGNAL ;
    PORT
      LAYER met3 ;
        RECT 418.560 265.890 419.560 266.170 ;
    END
  END dout[414]

  PIN dout[415]
    DIRECTION OUTPUT ;
    USE SIGNAL ;
    PORT
      LAYER met3 ;
        RECT 418.560 266.525 419.560 266.805 ;
    END
  END dout[415]

  PIN dout[416]
    DIRECTION OUTPUT ;
    USE SIGNAL ;
    PORT
      LAYER met3 ;
        RECT 418.560 267.160 419.560 267.440 ;
    END
  END dout[416]

  PIN dout[417]
    DIRECTION OUTPUT ;
    USE SIGNAL ;
    PORT
      LAYER met3 ;
        RECT 418.560 267.795 419.560 268.075 ;
    END
  END dout[417]

  PIN dout[418]
    DIRECTION OUTPUT ;
    USE SIGNAL ;
    PORT
      LAYER met3 ;
        RECT 418.560 268.430 419.560 268.710 ;
    END
  END dout[418]

  PIN dout[419]
    DIRECTION OUTPUT ;
    USE SIGNAL ;
    PORT
      LAYER met3 ;
        RECT 418.560 269.065 419.560 269.345 ;
    END
  END dout[419]

  PIN dout[420]
    DIRECTION OUTPUT ;
    USE SIGNAL ;
    PORT
      LAYER met3 ;
        RECT 418.560 269.700 419.560 269.980 ;
    END
  END dout[420]

  PIN dout[421]
    DIRECTION OUTPUT ;
    USE SIGNAL ;
    PORT
      LAYER met3 ;
        RECT 418.560 270.335 419.560 270.615 ;
    END
  END dout[421]

  PIN dout[422]
    DIRECTION OUTPUT ;
    USE SIGNAL ;
    PORT
      LAYER met3 ;
        RECT 418.560 270.970 419.560 271.250 ;
    END
  END dout[422]

  PIN dout[423]
    DIRECTION OUTPUT ;
    USE SIGNAL ;
    PORT
      LAYER met3 ;
        RECT 418.560 271.605 419.560 271.885 ;
    END
  END dout[423]

  PIN dout[424]
    DIRECTION OUTPUT ;
    USE SIGNAL ;
    PORT
      LAYER met3 ;
        RECT 418.560 272.240 419.560 272.520 ;
    END
  END dout[424]

  PIN dout[425]
    DIRECTION OUTPUT ;
    USE SIGNAL ;
    PORT
      LAYER met3 ;
        RECT 418.560 272.875 419.560 273.155 ;
    END
  END dout[425]

  PIN dout[426]
    DIRECTION OUTPUT ;
    USE SIGNAL ;
    PORT
      LAYER met3 ;
        RECT 418.560 273.510 419.560 273.790 ;
    END
  END dout[426]

  PIN dout[427]
    DIRECTION OUTPUT ;
    USE SIGNAL ;
    PORT
      LAYER met3 ;
        RECT 418.560 274.145 419.560 274.425 ;
    END
  END dout[427]

  PIN dout[428]
    DIRECTION OUTPUT ;
    USE SIGNAL ;
    PORT
      LAYER met3 ;
        RECT 418.560 274.780 419.560 275.060 ;
    END
  END dout[428]

  PIN dout[429]
    DIRECTION OUTPUT ;
    USE SIGNAL ;
    PORT
      LAYER met3 ;
        RECT 418.560 275.415 419.560 275.695 ;
    END
  END dout[429]

  PIN dout[430]
    DIRECTION OUTPUT ;
    USE SIGNAL ;
    PORT
      LAYER met3 ;
        RECT 418.560 276.050 419.560 276.330 ;
    END
  END dout[430]

  PIN dout[431]
    DIRECTION OUTPUT ;
    USE SIGNAL ;
    PORT
      LAYER met3 ;
        RECT 418.560 276.685 419.560 276.965 ;
    END
  END dout[431]

  PIN dout[432]
    DIRECTION OUTPUT ;
    USE SIGNAL ;
    PORT
      LAYER met3 ;
        RECT 418.560 277.320 419.560 277.600 ;
    END
  END dout[432]

  PIN dout[433]
    DIRECTION OUTPUT ;
    USE SIGNAL ;
    PORT
      LAYER met3 ;
        RECT 418.560 277.955 419.560 278.235 ;
    END
  END dout[433]

  PIN dout[434]
    DIRECTION OUTPUT ;
    USE SIGNAL ;
    PORT
      LAYER met3 ;
        RECT 418.560 278.590 419.560 278.870 ;
    END
  END dout[434]

  PIN dout[435]
    DIRECTION OUTPUT ;
    USE SIGNAL ;
    PORT
      LAYER met3 ;
        RECT 418.560 279.225 419.560 279.505 ;
    END
  END dout[435]

  PIN dout[436]
    DIRECTION OUTPUT ;
    USE SIGNAL ;
    PORT
      LAYER met3 ;
        RECT 418.560 279.860 419.560 280.140 ;
    END
  END dout[436]

  PIN dout[437]
    DIRECTION OUTPUT ;
    USE SIGNAL ;
    PORT
      LAYER met3 ;
        RECT 418.560 280.495 419.560 280.775 ;
    END
  END dout[437]

  PIN dout[438]
    DIRECTION OUTPUT ;
    USE SIGNAL ;
    PORT
      LAYER met3 ;
        RECT 418.560 281.130 419.560 281.410 ;
    END
  END dout[438]

  PIN dout[439]
    DIRECTION OUTPUT ;
    USE SIGNAL ;
    PORT
      LAYER met3 ;
        RECT 418.560 281.765 419.560 282.045 ;
    END
  END dout[439]

  PIN dout[440]
    DIRECTION OUTPUT ;
    USE SIGNAL ;
    PORT
      LAYER met3 ;
        RECT 418.560 282.400 419.560 282.680 ;
    END
  END dout[440]

  PIN dout[441]
    DIRECTION OUTPUT ;
    USE SIGNAL ;
    PORT
      LAYER met3 ;
        RECT 418.560 283.035 419.560 283.315 ;
    END
  END dout[441]

  PIN dout[442]
    DIRECTION OUTPUT ;
    USE SIGNAL ;
    PORT
      LAYER met3 ;
        RECT 418.560 283.670 419.560 283.950 ;
    END
  END dout[442]

  PIN dout[443]
    DIRECTION OUTPUT ;
    USE SIGNAL ;
    PORT
      LAYER met3 ;
        RECT 418.560 284.305 419.560 284.585 ;
    END
  END dout[443]

  PIN dout[444]
    DIRECTION OUTPUT ;
    USE SIGNAL ;
    PORT
      LAYER met3 ;
        RECT 418.560 284.940 419.560 285.220 ;
    END
  END dout[444]

  PIN dout[445]
    DIRECTION OUTPUT ;
    USE SIGNAL ;
    PORT
      LAYER met3 ;
        RECT 418.560 285.575 419.560 285.855 ;
    END
  END dout[445]

  PIN dout[446]
    DIRECTION OUTPUT ;
    USE SIGNAL ;
    PORT
      LAYER met3 ;
        RECT 418.560 286.210 419.560 286.490 ;
    END
  END dout[446]

  PIN dout[447]
    DIRECTION OUTPUT ;
    USE SIGNAL ;
    PORT
      LAYER met3 ;
        RECT 418.560 286.845 419.560 287.125 ;
    END
  END dout[447]

  PIN dout[448]
    DIRECTION OUTPUT ;
    USE SIGNAL ;
    PORT
      LAYER met3 ;
        RECT 418.560 287.480 419.560 287.760 ;
    END
  END dout[448]

  PIN dout[449]
    DIRECTION OUTPUT ;
    USE SIGNAL ;
    PORT
      LAYER met3 ;
        RECT 418.560 288.115 419.560 288.395 ;
    END
  END dout[449]

  PIN dout[450]
    DIRECTION OUTPUT ;
    USE SIGNAL ;
    PORT
      LAYER met3 ;
        RECT 418.560 288.750 419.560 289.030 ;
    END
  END dout[450]

  PIN dout[451]
    DIRECTION OUTPUT ;
    USE SIGNAL ;
    PORT
      LAYER met3 ;
        RECT 418.560 289.385 419.560 289.665 ;
    END
  END dout[451]

  PIN dout[452]
    DIRECTION OUTPUT ;
    USE SIGNAL ;
    PORT
      LAYER met3 ;
        RECT 418.560 290.020 419.560 290.300 ;
    END
  END dout[452]

  PIN dout[453]
    DIRECTION OUTPUT ;
    USE SIGNAL ;
    PORT
      LAYER met3 ;
        RECT 418.560 290.655 419.560 290.935 ;
    END
  END dout[453]

  PIN dout[454]
    DIRECTION OUTPUT ;
    USE SIGNAL ;
    PORT
      LAYER met3 ;
        RECT 418.560 291.290 419.560 291.570 ;
    END
  END dout[454]

  PIN dout[455]
    DIRECTION OUTPUT ;
    USE SIGNAL ;
    PORT
      LAYER met3 ;
        RECT 418.560 291.925 419.560 292.205 ;
    END
  END dout[455]

  PIN dout[456]
    DIRECTION OUTPUT ;
    USE SIGNAL ;
    PORT
      LAYER met3 ;
        RECT 418.560 292.560 419.560 292.840 ;
    END
  END dout[456]

  PIN dout[457]
    DIRECTION OUTPUT ;
    USE SIGNAL ;
    PORT
      LAYER met3 ;
        RECT 418.560 293.195 419.560 293.475 ;
    END
  END dout[457]

  PIN dout[458]
    DIRECTION OUTPUT ;
    USE SIGNAL ;
    PORT
      LAYER met3 ;
        RECT 418.560 293.830 419.560 294.110 ;
    END
  END dout[458]

  PIN dout[459]
    DIRECTION OUTPUT ;
    USE SIGNAL ;
    PORT
      LAYER met3 ;
        RECT 418.560 294.465 419.560 294.745 ;
    END
  END dout[459]

  PIN dout[460]
    DIRECTION OUTPUT ;
    USE SIGNAL ;
    PORT
      LAYER met3 ;
        RECT 418.560 295.100 419.560 295.380 ;
    END
  END dout[460]

  PIN dout[461]
    DIRECTION OUTPUT ;
    USE SIGNAL ;
    PORT
      LAYER met3 ;
        RECT 418.560 295.735 419.560 296.015 ;
    END
  END dout[461]

  PIN dout[462]
    DIRECTION OUTPUT ;
    USE SIGNAL ;
    PORT
      LAYER met3 ;
        RECT 418.560 296.370 419.560 296.650 ;
    END
  END dout[462]

  PIN dout[463]
    DIRECTION OUTPUT ;
    USE SIGNAL ;
    PORT
      LAYER met3 ;
        RECT 418.560 297.005 419.560 297.285 ;
    END
  END dout[463]

  PIN dout[464]
    DIRECTION OUTPUT ;
    USE SIGNAL ;
    PORT
      LAYER met3 ;
        RECT 418.560 297.640 419.560 297.920 ;
    END
  END dout[464]

  PIN dout[465]
    DIRECTION OUTPUT ;
    USE SIGNAL ;
    PORT
      LAYER met3 ;
        RECT 418.560 298.275 419.560 298.555 ;
    END
  END dout[465]

  PIN dout[466]
    DIRECTION OUTPUT ;
    USE SIGNAL ;
    PORT
      LAYER met3 ;
        RECT 418.560 298.910 419.560 299.190 ;
    END
  END dout[466]

  PIN dout[467]
    DIRECTION OUTPUT ;
    USE SIGNAL ;
    PORT
      LAYER met3 ;
        RECT 418.560 299.545 419.560 299.825 ;
    END
  END dout[467]

  PIN dout[468]
    DIRECTION OUTPUT ;
    USE SIGNAL ;
    PORT
      LAYER met3 ;
        RECT 418.560 300.180 419.560 300.460 ;
    END
  END dout[468]

  PIN dout[469]
    DIRECTION OUTPUT ;
    USE SIGNAL ;
    PORT
      LAYER met3 ;
        RECT 418.560 300.815 419.560 301.095 ;
    END
  END dout[469]

  PIN dout[470]
    DIRECTION OUTPUT ;
    USE SIGNAL ;
    PORT
      LAYER met3 ;
        RECT 418.560 301.450 419.560 301.730 ;
    END
  END dout[470]

  PIN dout[471]
    DIRECTION OUTPUT ;
    USE SIGNAL ;
    PORT
      LAYER met3 ;
        RECT 418.560 302.085 419.560 302.365 ;
    END
  END dout[471]

  PIN dout[472]
    DIRECTION OUTPUT ;
    USE SIGNAL ;
    PORT
      LAYER met3 ;
        RECT 418.560 302.720 419.560 303.000 ;
    END
  END dout[472]

  PIN dout[473]
    DIRECTION OUTPUT ;
    USE SIGNAL ;
    PORT
      LAYER met3 ;
        RECT 418.560 303.355 419.560 303.635 ;
    END
  END dout[473]

  PIN dout[474]
    DIRECTION OUTPUT ;
    USE SIGNAL ;
    PORT
      LAYER met3 ;
        RECT 418.560 303.990 419.560 304.270 ;
    END
  END dout[474]

  PIN dout[475]
    DIRECTION OUTPUT ;
    USE SIGNAL ;
    PORT
      LAYER met3 ;
        RECT 418.560 304.625 419.560 304.905 ;
    END
  END dout[475]

  PIN dout[476]
    DIRECTION OUTPUT ;
    USE SIGNAL ;
    PORT
      LAYER met3 ;
        RECT 418.560 305.260 419.560 305.540 ;
    END
  END dout[476]

  PIN dout[477]
    DIRECTION OUTPUT ;
    USE SIGNAL ;
    PORT
      LAYER met3 ;
        RECT 418.560 305.895 419.560 306.175 ;
    END
  END dout[477]

  PIN dout[478]
    DIRECTION OUTPUT ;
    USE SIGNAL ;
    PORT
      LAYER met3 ;
        RECT 418.560 306.530 419.560 306.810 ;
    END
  END dout[478]

  PIN dout[479]
    DIRECTION OUTPUT ;
    USE SIGNAL ;
    PORT
      LAYER met3 ;
        RECT 418.560 307.165 419.560 307.445 ;
    END
  END dout[479]

  PIN dout[480]
    DIRECTION OUTPUT ;
    USE SIGNAL ;
    PORT
      LAYER met3 ;
        RECT 418.560 307.800 419.560 308.080 ;
    END
  END dout[480]

  PIN dout[481]
    DIRECTION OUTPUT ;
    USE SIGNAL ;
    PORT
      LAYER met3 ;
        RECT 418.560 308.435 419.560 308.715 ;
    END
  END dout[481]

  PIN dout[482]
    DIRECTION OUTPUT ;
    USE SIGNAL ;
    PORT
      LAYER met3 ;
        RECT 418.560 309.070 419.560 309.350 ;
    END
  END dout[482]

  PIN dout[483]
    DIRECTION OUTPUT ;
    USE SIGNAL ;
    PORT
      LAYER met3 ;
        RECT 418.560 309.705 419.560 309.985 ;
    END
  END dout[483]

  PIN dout[484]
    DIRECTION OUTPUT ;
    USE SIGNAL ;
    PORT
      LAYER met3 ;
        RECT 418.560 310.340 419.560 310.620 ;
    END
  END dout[484]

  PIN dout[485]
    DIRECTION OUTPUT ;
    USE SIGNAL ;
    PORT
      LAYER met3 ;
        RECT 418.560 310.975 419.560 311.255 ;
    END
  END dout[485]

  PIN dout[486]
    DIRECTION OUTPUT ;
    USE SIGNAL ;
    PORT
      LAYER met3 ;
        RECT 418.560 311.610 419.560 311.890 ;
    END
  END dout[486]

  PIN dout[487]
    DIRECTION OUTPUT ;
    USE SIGNAL ;
    PORT
      LAYER met3 ;
        RECT 418.560 312.245 419.560 312.525 ;
    END
  END dout[487]

  PIN dout[488]
    DIRECTION OUTPUT ;
    USE SIGNAL ;
    PORT
      LAYER met3 ;
        RECT 418.560 312.880 419.560 313.160 ;
    END
  END dout[488]

  PIN dout[489]
    DIRECTION OUTPUT ;
    USE SIGNAL ;
    PORT
      LAYER met3 ;
        RECT 418.560 313.515 419.560 313.795 ;
    END
  END dout[489]

  PIN dout[490]
    DIRECTION OUTPUT ;
    USE SIGNAL ;
    PORT
      LAYER met3 ;
        RECT 418.560 314.150 419.560 314.430 ;
    END
  END dout[490]

  PIN dout[491]
    DIRECTION OUTPUT ;
    USE SIGNAL ;
    PORT
      LAYER met3 ;
        RECT 418.560 314.785 419.560 315.065 ;
    END
  END dout[491]

  PIN dout[492]
    DIRECTION OUTPUT ;
    USE SIGNAL ;
    PORT
      LAYER met3 ;
        RECT 418.560 315.420 419.560 315.700 ;
    END
  END dout[492]

  PIN dout[493]
    DIRECTION OUTPUT ;
    USE SIGNAL ;
    PORT
      LAYER met3 ;
        RECT 418.560 316.055 419.560 316.335 ;
    END
  END dout[493]

  PIN dout[494]
    DIRECTION OUTPUT ;
    USE SIGNAL ;
    PORT
      LAYER met3 ;
        RECT 418.560 316.690 419.560 316.970 ;
    END
  END dout[494]

  PIN dout[495]
    DIRECTION OUTPUT ;
    USE SIGNAL ;
    PORT
      LAYER met3 ;
        RECT 418.560 317.325 419.560 317.605 ;
    END
  END dout[495]

  PIN dout[496]
    DIRECTION OUTPUT ;
    USE SIGNAL ;
    PORT
      LAYER met3 ;
        RECT 418.560 317.960 419.560 318.240 ;
    END
  END dout[496]

  PIN dout[497]
    DIRECTION OUTPUT ;
    USE SIGNAL ;
    PORT
      LAYER met3 ;
        RECT 418.560 318.595 419.560 318.875 ;
    END
  END dout[497]

  PIN dout[498]
    DIRECTION OUTPUT ;
    USE SIGNAL ;
    PORT
      LAYER met3 ;
        RECT 418.560 319.230 419.560 319.510 ;
    END
  END dout[498]

  PIN dout[499]
    DIRECTION OUTPUT ;
    USE SIGNAL ;
    PORT
      LAYER met3 ;
        RECT 418.560 319.865 419.560 320.145 ;
    END
  END dout[499]

  PIN dout[500]
    DIRECTION OUTPUT ;
    USE SIGNAL ;
    PORT
      LAYER met3 ;
        RECT 418.560 320.500 419.560 320.780 ;
    END
  END dout[500]

  PIN dout[501]
    DIRECTION OUTPUT ;
    USE SIGNAL ;
    PORT
      LAYER met3 ;
        RECT 418.560 321.135 419.560 321.415 ;
    END
  END dout[501]

  PIN dout[502]
    DIRECTION OUTPUT ;
    USE SIGNAL ;
    PORT
      LAYER met3 ;
        RECT 418.560 321.770 419.560 322.050 ;
    END
  END dout[502]

  PIN dout[503]
    DIRECTION OUTPUT ;
    USE SIGNAL ;
    PORT
      LAYER met3 ;
        RECT 418.560 322.405 419.560 322.685 ;
    END
  END dout[503]

  PIN dout[504]
    DIRECTION OUTPUT ;
    USE SIGNAL ;
    PORT
      LAYER met3 ;
        RECT 418.560 323.040 419.560 323.320 ;
    END
  END dout[504]

  PIN dout[505]
    DIRECTION OUTPUT ;
    USE SIGNAL ;
    PORT
      LAYER met3 ;
        RECT 418.560 323.675 419.560 323.955 ;
    END
  END dout[505]

  PIN dout[506]
    DIRECTION OUTPUT ;
    USE SIGNAL ;
    PORT
      LAYER met3 ;
        RECT 418.560 324.310 419.560 324.590 ;
    END
  END dout[506]

  PIN dout[507]
    DIRECTION OUTPUT ;
    USE SIGNAL ;
    PORT
      LAYER met3 ;
        RECT 418.560 324.945 419.560 325.225 ;
    END
  END dout[507]

  PIN dout[508]
    DIRECTION OUTPUT ;
    USE SIGNAL ;
    PORT
      LAYER met3 ;
        RECT 418.560 325.580 419.560 325.860 ;
    END
  END dout[508]

  PIN dout[509]
    DIRECTION OUTPUT ;
    USE SIGNAL ;
    PORT
      LAYER met3 ;
        RECT 418.560 326.215 419.560 326.495 ;
    END
  END dout[509]

  PIN dout[510]
    DIRECTION OUTPUT ;
    USE SIGNAL ;
    PORT
      LAYER met3 ;
        RECT 418.560 326.850 419.560 327.130 ;
    END
  END dout[510]

  PIN dout[511]
    DIRECTION OUTPUT ;
    USE SIGNAL ;
    PORT
      LAYER met3 ;
        RECT 418.560 327.485 419.560 327.765 ;
    END
  END dout[511]

  PIN dout[512]
    DIRECTION OUTPUT ;
    USE SIGNAL ;
    PORT
      LAYER met3 ;
        RECT 418.560 328.120 419.560 328.400 ;
    END
  END dout[512]

  PIN dout[513]
    DIRECTION OUTPUT ;
    USE SIGNAL ;
    PORT
      LAYER met3 ;
        RECT 418.560 328.755 419.560 329.035 ;
    END
  END dout[513]

  PIN dout[514]
    DIRECTION OUTPUT ;
    USE SIGNAL ;
    PORT
      LAYER met3 ;
        RECT 418.560 329.390 419.560 329.670 ;
    END
  END dout[514]

  PIN dout[515]
    DIRECTION OUTPUT ;
    USE SIGNAL ;
    PORT
      LAYER met3 ;
        RECT 418.560 330.025 419.560 330.305 ;
    END
  END dout[515]

  PIN dout[516]
    DIRECTION OUTPUT ;
    USE SIGNAL ;
    PORT
      LAYER met3 ;
        RECT 418.560 330.660 419.560 330.940 ;
    END
  END dout[516]

  PIN dout[517]
    DIRECTION OUTPUT ;
    USE SIGNAL ;
    PORT
      LAYER met3 ;
        RECT 418.560 331.295 419.560 331.575 ;
    END
  END dout[517]

  PIN dout[518]
    DIRECTION OUTPUT ;
    USE SIGNAL ;
    PORT
      LAYER met3 ;
        RECT 418.560 331.930 419.560 332.210 ;
    END
  END dout[518]

  PIN dout[519]
    DIRECTION OUTPUT ;
    USE SIGNAL ;
    PORT
      LAYER met3 ;
        RECT 418.560 332.565 419.560 332.845 ;
    END
  END dout[519]

  PIN dout[520]
    DIRECTION OUTPUT ;
    USE SIGNAL ;
    PORT
      LAYER met3 ;
        RECT 418.560 333.200 419.560 333.480 ;
    END
  END dout[520]

  PIN dout[521]
    DIRECTION OUTPUT ;
    USE SIGNAL ;
    PORT
      LAYER met3 ;
        RECT 418.560 333.835 419.560 334.115 ;
    END
  END dout[521]

  PIN dout[522]
    DIRECTION OUTPUT ;
    USE SIGNAL ;
    PORT
      LAYER met3 ;
        RECT 418.560 334.470 419.560 334.750 ;
    END
  END dout[522]

  PIN dout[523]
    DIRECTION OUTPUT ;
    USE SIGNAL ;
    PORT
      LAYER met3 ;
        RECT 418.560 335.105 419.560 335.385 ;
    END
  END dout[523]

  PIN dout[524]
    DIRECTION OUTPUT ;
    USE SIGNAL ;
    PORT
      LAYER met3 ;
        RECT 418.560 335.740 419.560 336.020 ;
    END
  END dout[524]

  PIN dout[525]
    DIRECTION OUTPUT ;
    USE SIGNAL ;
    PORT
      LAYER met3 ;
        RECT 418.560 336.375 419.560 336.655 ;
    END
  END dout[525]

  PIN dout[526]
    DIRECTION OUTPUT ;
    USE SIGNAL ;
    PORT
      LAYER met3 ;
        RECT 418.560 337.010 419.560 337.290 ;
    END
  END dout[526]

  PIN dout[527]
    DIRECTION OUTPUT ;
    USE SIGNAL ;
    PORT
      LAYER met3 ;
        RECT 418.560 337.645 419.560 337.925 ;
    END
  END dout[527]

  PIN dout[528]
    DIRECTION OUTPUT ;
    USE SIGNAL ;
    PORT
      LAYER met3 ;
        RECT 418.560 338.280 419.560 338.560 ;
    END
  END dout[528]

  PIN dout[529]
    DIRECTION OUTPUT ;
    USE SIGNAL ;
    PORT
      LAYER met3 ;
        RECT 418.560 338.915 419.560 339.195 ;
    END
  END dout[529]

  PIN dout[530]
    DIRECTION OUTPUT ;
    USE SIGNAL ;
    PORT
      LAYER met3 ;
        RECT 418.560 339.550 419.560 339.830 ;
    END
  END dout[530]

  PIN dout[531]
    DIRECTION OUTPUT ;
    USE SIGNAL ;
    PORT
      LAYER met3 ;
        RECT 418.560 340.185 419.560 340.465 ;
    END
  END dout[531]

  PIN dout[532]
    DIRECTION OUTPUT ;
    USE SIGNAL ;
    PORT
      LAYER met3 ;
        RECT 418.560 340.820 419.560 341.100 ;
    END
  END dout[532]

  PIN dout[533]
    DIRECTION OUTPUT ;
    USE SIGNAL ;
    PORT
      LAYER met3 ;
        RECT 418.560 341.455 419.560 341.735 ;
    END
  END dout[533]

  PIN dout[534]
    DIRECTION OUTPUT ;
    USE SIGNAL ;
    PORT
      LAYER met3 ;
        RECT 418.560 342.090 419.560 342.370 ;
    END
  END dout[534]

  PIN dout[535]
    DIRECTION OUTPUT ;
    USE SIGNAL ;
    PORT
      LAYER met3 ;
        RECT 418.560 342.725 419.560 343.005 ;
    END
  END dout[535]

  PIN dout[536]
    DIRECTION OUTPUT ;
    USE SIGNAL ;
    PORT
      LAYER met3 ;
        RECT 418.560 343.360 419.560 343.640 ;
    END
  END dout[536]

  PIN dout[537]
    DIRECTION OUTPUT ;
    USE SIGNAL ;
    PORT
      LAYER met3 ;
        RECT 418.560 343.995 419.560 344.275 ;
    END
  END dout[537]

  PIN dout[538]
    DIRECTION OUTPUT ;
    USE SIGNAL ;
    PORT
      LAYER met3 ;
        RECT 418.560 344.630 419.560 344.910 ;
    END
  END dout[538]

  PIN dout[539]
    DIRECTION OUTPUT ;
    USE SIGNAL ;
    PORT
      LAYER met3 ;
        RECT 418.560 345.265 419.560 345.545 ;
    END
  END dout[539]

  PIN dout[540]
    DIRECTION OUTPUT ;
    USE SIGNAL ;
    PORT
      LAYER met3 ;
        RECT 418.560 345.900 419.560 346.180 ;
    END
  END dout[540]

  PIN dout[541]
    DIRECTION OUTPUT ;
    USE SIGNAL ;
    PORT
      LAYER met3 ;
        RECT 418.560 346.535 419.560 346.815 ;
    END
  END dout[541]

  PIN dout[542]
    DIRECTION OUTPUT ;
    USE SIGNAL ;
    PORT
      LAYER met3 ;
        RECT 418.560 347.170 419.560 347.450 ;
    END
  END dout[542]

  PIN dout[543]
    DIRECTION OUTPUT ;
    USE SIGNAL ;
    PORT
      LAYER met3 ;
        RECT 418.560 347.805 419.560 348.085 ;
    END
  END dout[543]

  PIN dout[544]
    DIRECTION OUTPUT ;
    USE SIGNAL ;
    PORT
      LAYER met3 ;
        RECT 418.560 348.440 419.560 348.720 ;
    END
  END dout[544]

  PIN dout[545]
    DIRECTION OUTPUT ;
    USE SIGNAL ;
    PORT
      LAYER met3 ;
        RECT 418.560 349.075 419.560 349.355 ;
    END
  END dout[545]

  PIN dout[546]
    DIRECTION OUTPUT ;
    USE SIGNAL ;
    PORT
      LAYER met3 ;
        RECT 418.560 349.710 419.560 349.990 ;
    END
  END dout[546]

  PIN dout[547]
    DIRECTION OUTPUT ;
    USE SIGNAL ;
    PORT
      LAYER met3 ;
        RECT 418.560 350.345 419.560 350.625 ;
    END
  END dout[547]

  PIN dout[548]
    DIRECTION OUTPUT ;
    USE SIGNAL ;
    PORT
      LAYER met3 ;
        RECT 418.560 350.980 419.560 351.260 ;
    END
  END dout[548]

  PIN dout[549]
    DIRECTION OUTPUT ;
    USE SIGNAL ;
    PORT
      LAYER met3 ;
        RECT 418.560 351.615 419.560 351.895 ;
    END
  END dout[549]

  PIN dout[550]
    DIRECTION OUTPUT ;
    USE SIGNAL ;
    PORT
      LAYER met3 ;
        RECT 418.560 352.250 419.560 352.530 ;
    END
  END dout[550]

  PIN dout[551]
    DIRECTION OUTPUT ;
    USE SIGNAL ;
    PORT
      LAYER met3 ;
        RECT 418.560 352.885 419.560 353.165 ;
    END
  END dout[551]

  PIN dout[552]
    DIRECTION OUTPUT ;
    USE SIGNAL ;
    PORT
      LAYER met3 ;
        RECT 418.560 353.520 419.560 353.800 ;
    END
  END dout[552]

  PIN dout[553]
    DIRECTION OUTPUT ;
    USE SIGNAL ;
    PORT
      LAYER met3 ;
        RECT 418.560 354.155 419.560 354.435 ;
    END
  END dout[553]

  PIN dout[554]
    DIRECTION OUTPUT ;
    USE SIGNAL ;
    PORT
      LAYER met3 ;
        RECT 418.560 354.790 419.560 355.070 ;
    END
  END dout[554]

  PIN dout[555]
    DIRECTION OUTPUT ;
    USE SIGNAL ;
    PORT
      LAYER met3 ;
        RECT 418.560 355.425 419.560 355.705 ;
    END
  END dout[555]

  PIN dout[556]
    DIRECTION OUTPUT ;
    USE SIGNAL ;
    PORT
      LAYER met3 ;
        RECT 418.560 356.060 419.560 356.340 ;
    END
  END dout[556]

  PIN dout[557]
    DIRECTION OUTPUT ;
    USE SIGNAL ;
    PORT
      LAYER met3 ;
        RECT 418.560 356.695 419.560 356.975 ;
    END
  END dout[557]

  PIN dout[558]
    DIRECTION OUTPUT ;
    USE SIGNAL ;
    PORT
      LAYER met3 ;
        RECT 418.560 357.330 419.560 357.610 ;
    END
  END dout[558]

  PIN dout[559]
    DIRECTION OUTPUT ;
    USE SIGNAL ;
    PORT
      LAYER met3 ;
        RECT 418.560 357.965 419.560 358.245 ;
    END
  END dout[559]

  PIN dout[560]
    DIRECTION OUTPUT ;
    USE SIGNAL ;
    PORT
      LAYER met3 ;
        RECT 418.560 358.600 419.560 358.880 ;
    END
  END dout[560]

  PIN dout[561]
    DIRECTION OUTPUT ;
    USE SIGNAL ;
    PORT
      LAYER met3 ;
        RECT 418.560 359.235 419.560 359.515 ;
    END
  END dout[561]

  PIN dout[562]
    DIRECTION OUTPUT ;
    USE SIGNAL ;
    PORT
      LAYER met3 ;
        RECT 418.560 359.870 419.560 360.150 ;
    END
  END dout[562]

  PIN dout[563]
    DIRECTION OUTPUT ;
    USE SIGNAL ;
    PORT
      LAYER met3 ;
        RECT 418.560 360.505 419.560 360.785 ;
    END
  END dout[563]

  PIN dout[564]
    DIRECTION OUTPUT ;
    USE SIGNAL ;
    PORT
      LAYER met3 ;
        RECT 418.560 361.140 419.560 361.420 ;
    END
  END dout[564]

  PIN dout[565]
    DIRECTION OUTPUT ;
    USE SIGNAL ;
    PORT
      LAYER met3 ;
        RECT 418.560 361.775 419.560 362.055 ;
    END
  END dout[565]

  PIN dout[566]
    DIRECTION OUTPUT ;
    USE SIGNAL ;
    PORT
      LAYER met3 ;
        RECT 418.560 362.410 419.560 362.690 ;
    END
  END dout[566]

  PIN dout[567]
    DIRECTION OUTPUT ;
    USE SIGNAL ;
    PORT
      LAYER met3 ;
        RECT 418.560 363.045 419.560 363.325 ;
    END
  END dout[567]

  PIN dout[568]
    DIRECTION OUTPUT ;
    USE SIGNAL ;
    PORT
      LAYER met3 ;
        RECT 418.560 363.680 419.560 363.960 ;
    END
  END dout[568]

  PIN dout[569]
    DIRECTION OUTPUT ;
    USE SIGNAL ;
    PORT
      LAYER met3 ;
        RECT 418.560 364.315 419.560 364.595 ;
    END
  END dout[569]

  PIN dout[570]
    DIRECTION OUTPUT ;
    USE SIGNAL ;
    PORT
      LAYER met3 ;
        RECT 418.560 364.950 419.560 365.230 ;
    END
  END dout[570]

  PIN dout[571]
    DIRECTION OUTPUT ;
    USE SIGNAL ;
    PORT
      LAYER met3 ;
        RECT 418.560 365.585 419.560 365.865 ;
    END
  END dout[571]

  PIN dout[572]
    DIRECTION OUTPUT ;
    USE SIGNAL ;
    PORT
      LAYER met3 ;
        RECT 418.560 366.220 419.560 366.500 ;
    END
  END dout[572]

  PIN dout[573]
    DIRECTION OUTPUT ;
    USE SIGNAL ;
    PORT
      LAYER met3 ;
        RECT 418.560 366.855 419.560 367.135 ;
    END
  END dout[573]

  PIN dout[574]
    DIRECTION OUTPUT ;
    USE SIGNAL ;
    PORT
      LAYER met3 ;
        RECT 418.560 367.490 419.560 367.770 ;
    END
  END dout[574]

  PIN dout[575]
    DIRECTION OUTPUT ;
    USE SIGNAL ;
    PORT
      LAYER met3 ;
        RECT 418.560 368.125 419.560 368.405 ;
    END
  END dout[575]

  PIN dout[576]
    DIRECTION OUTPUT ;
    USE SIGNAL ;
    PORT
      LAYER met3 ;
        RECT 418.560 368.760 419.560 369.040 ;
    END
  END dout[576]

  PIN dout[577]
    DIRECTION OUTPUT ;
    USE SIGNAL ;
    PORT
      LAYER met3 ;
        RECT 418.560 369.395 419.560 369.675 ;
    END
  END dout[577]

  PIN dout[578]
    DIRECTION OUTPUT ;
    USE SIGNAL ;
    PORT
      LAYER met3 ;
        RECT 418.560 370.030 419.560 370.310 ;
    END
  END dout[578]

  PIN dout[579]
    DIRECTION OUTPUT ;
    USE SIGNAL ;
    PORT
      LAYER met3 ;
        RECT 418.560 370.665 419.560 370.945 ;
    END
  END dout[579]

  PIN dout[580]
    DIRECTION OUTPUT ;
    USE SIGNAL ;
    PORT
      LAYER met3 ;
        RECT 418.560 371.300 419.560 371.580 ;
    END
  END dout[580]

  PIN dout[581]
    DIRECTION OUTPUT ;
    USE SIGNAL ;
    PORT
      LAYER met3 ;
        RECT 418.560 371.935 419.560 372.215 ;
    END
  END dout[581]

  PIN dout[582]
    DIRECTION OUTPUT ;
    USE SIGNAL ;
    PORT
      LAYER met3 ;
        RECT 418.560 372.570 419.560 372.850 ;
    END
  END dout[582]

  PIN dout[583]
    DIRECTION OUTPUT ;
    USE SIGNAL ;
    PORT
      LAYER met3 ;
        RECT 418.560 373.205 419.560 373.485 ;
    END
  END dout[583]

  PIN dout[584]
    DIRECTION OUTPUT ;
    USE SIGNAL ;
    PORT
      LAYER met3 ;
        RECT 418.560 373.840 419.560 374.120 ;
    END
  END dout[584]

  PIN dout[585]
    DIRECTION OUTPUT ;
    USE SIGNAL ;
    PORT
      LAYER met3 ;
        RECT 418.560 374.475 419.560 374.755 ;
    END
  END dout[585]

  PIN dout[586]
    DIRECTION OUTPUT ;
    USE SIGNAL ;
    PORT
      LAYER met3 ;
        RECT 418.560 375.110 419.560 375.390 ;
    END
  END dout[586]

  PIN dout[587]
    DIRECTION OUTPUT ;
    USE SIGNAL ;
    PORT
      LAYER met3 ;
        RECT 418.560 375.745 419.560 376.025 ;
    END
  END dout[587]

  PIN dout[588]
    DIRECTION OUTPUT ;
    USE SIGNAL ;
    PORT
      LAYER met3 ;
        RECT 418.560 376.380 419.560 376.660 ;
    END
  END dout[588]

  PIN dout[589]
    DIRECTION OUTPUT ;
    USE SIGNAL ;
    PORT
      LAYER met3 ;
        RECT 418.560 377.015 419.560 377.295 ;
    END
  END dout[589]

  PIN dout[590]
    DIRECTION OUTPUT ;
    USE SIGNAL ;
    PORT
      LAYER met3 ;
        RECT 418.560 377.650 419.560 377.930 ;
    END
  END dout[590]

  PIN dout[591]
    DIRECTION OUTPUT ;
    USE SIGNAL ;
    PORT
      LAYER met3 ;
        RECT 418.560 378.285 419.560 378.565 ;
    END
  END dout[591]

  PIN dout[592]
    DIRECTION OUTPUT ;
    USE SIGNAL ;
    PORT
      LAYER met3 ;
        RECT 418.560 378.920 419.560 379.200 ;
    END
  END dout[592]

  PIN dout[593]
    DIRECTION OUTPUT ;
    USE SIGNAL ;
    PORT
      LAYER met3 ;
        RECT 418.560 379.555 419.560 379.835 ;
    END
  END dout[593]

  PIN dout[594]
    DIRECTION OUTPUT ;
    USE SIGNAL ;
    PORT
      LAYER met3 ;
        RECT 418.560 380.190 419.560 380.470 ;
    END
  END dout[594]

  PIN dout[595]
    DIRECTION OUTPUT ;
    USE SIGNAL ;
    PORT
      LAYER met3 ;
        RECT 418.560 380.825 419.560 381.105 ;
    END
  END dout[595]

  PIN dout[596]
    DIRECTION OUTPUT ;
    USE SIGNAL ;
    PORT
      LAYER met3 ;
        RECT 418.560 381.460 419.560 381.740 ;
    END
  END dout[596]

  PIN dout[597]
    DIRECTION OUTPUT ;
    USE SIGNAL ;
    PORT
      LAYER met3 ;
        RECT 418.560 382.095 419.560 382.375 ;
    END
  END dout[597]

  PIN dout[598]
    DIRECTION OUTPUT ;
    USE SIGNAL ;
    PORT
      LAYER met3 ;
        RECT 418.560 382.730 419.560 383.010 ;
    END
  END dout[598]

  PIN dout[599]
    DIRECTION OUTPUT ;
    USE SIGNAL ;
    PORT
      LAYER met3 ;
        RECT 418.560 383.365 419.560 383.645 ;
    END
  END dout[599]

  PIN dout[600]
    DIRECTION OUTPUT ;
    USE SIGNAL ;
    PORT
      LAYER met3 ;
        RECT 418.560 384.000 419.560 384.280 ;
    END
  END dout[600]

  PIN dout[601]
    DIRECTION OUTPUT ;
    USE SIGNAL ;
    PORT
      LAYER met3 ;
        RECT 418.560 384.635 419.560 384.915 ;
    END
  END dout[601]

  PIN dout[602]
    DIRECTION OUTPUT ;
    USE SIGNAL ;
    PORT
      LAYER met3 ;
        RECT 418.560 385.270 419.560 385.550 ;
    END
  END dout[602]

  PIN dout[603]
    DIRECTION OUTPUT ;
    USE SIGNAL ;
    PORT
      LAYER met3 ;
        RECT 418.560 385.905 419.560 386.185 ;
    END
  END dout[603]

  PIN dout[604]
    DIRECTION OUTPUT ;
    USE SIGNAL ;
    PORT
      LAYER met3 ;
        RECT 418.560 386.540 419.560 386.820 ;
    END
  END dout[604]

  PIN dout[605]
    DIRECTION OUTPUT ;
    USE SIGNAL ;
    PORT
      LAYER met3 ;
        RECT 418.560 387.175 419.560 387.455 ;
    END
  END dout[605]

  PIN dout[606]
    DIRECTION OUTPUT ;
    USE SIGNAL ;
    PORT
      LAYER met3 ;
        RECT 418.560 387.810 419.560 388.090 ;
    END
  END dout[606]

  PIN dout[607]
    DIRECTION OUTPUT ;
    USE SIGNAL ;
    PORT
      LAYER met3 ;
        RECT 418.560 388.445 419.560 388.725 ;
    END
  END dout[607]

  PIN dout[608]
    DIRECTION OUTPUT ;
    USE SIGNAL ;
    PORT
      LAYER met3 ;
        RECT 418.560 389.080 419.560 389.360 ;
    END
  END dout[608]

  PIN dout[609]
    DIRECTION OUTPUT ;
    USE SIGNAL ;
    PORT
      LAYER met3 ;
        RECT 418.560 389.715 419.560 389.995 ;
    END
  END dout[609]

  PIN dout[610]
    DIRECTION OUTPUT ;
    USE SIGNAL ;
    PORT
      LAYER met3 ;
        RECT 418.560 390.350 419.560 390.630 ;
    END
  END dout[610]

  PIN dout[611]
    DIRECTION OUTPUT ;
    USE SIGNAL ;
    PORT
      LAYER met3 ;
        RECT 418.560 390.985 419.560 391.265 ;
    END
  END dout[611]

  PIN dout[612]
    DIRECTION OUTPUT ;
    USE SIGNAL ;
    PORT
      LAYER met3 ;
        RECT 418.560 391.620 419.560 391.900 ;
    END
  END dout[612]

  PIN dout[613]
    DIRECTION OUTPUT ;
    USE SIGNAL ;
    PORT
      LAYER met3 ;
        RECT 418.560 392.255 419.560 392.535 ;
    END
  END dout[613]

  PIN dout[614]
    DIRECTION OUTPUT ;
    USE SIGNAL ;
    PORT
      LAYER met3 ;
        RECT 418.560 392.890 419.560 393.170 ;
    END
  END dout[614]

  PIN dout[615]
    DIRECTION OUTPUT ;
    USE SIGNAL ;
    PORT
      LAYER met3 ;
        RECT 418.560 393.525 419.560 393.805 ;
    END
  END dout[615]

  PIN dout[616]
    DIRECTION OUTPUT ;
    USE SIGNAL ;
    PORT
      LAYER met3 ;
        RECT 418.560 394.160 419.560 394.440 ;
    END
  END dout[616]

  PIN dout[617]
    DIRECTION OUTPUT ;
    USE SIGNAL ;
    PORT
      LAYER met3 ;
        RECT 418.560 394.795 419.560 395.075 ;
    END
  END dout[617]

  PIN dout[618]
    DIRECTION OUTPUT ;
    USE SIGNAL ;
    PORT
      LAYER met3 ;
        RECT 418.560 395.430 419.560 395.710 ;
    END
  END dout[618]

  PIN dout[619]
    DIRECTION OUTPUT ;
    USE SIGNAL ;
    PORT
      LAYER met3 ;
        RECT 418.560 396.065 419.560 396.345 ;
    END
  END dout[619]

  PIN dout[620]
    DIRECTION OUTPUT ;
    USE SIGNAL ;
    PORT
      LAYER met3 ;
        RECT 418.560 396.700 419.560 396.980 ;
    END
  END dout[620]

  PIN dout[621]
    DIRECTION OUTPUT ;
    USE SIGNAL ;
    PORT
      LAYER met3 ;
        RECT 418.560 397.335 419.560 397.615 ;
    END
  END dout[621]

  PIN dout[622]
    DIRECTION OUTPUT ;
    USE SIGNAL ;
    PORT
      LAYER met3 ;
        RECT 418.560 397.970 419.560 398.250 ;
    END
  END dout[622]

  PIN dout[623]
    DIRECTION OUTPUT ;
    USE SIGNAL ;
    PORT
      LAYER met3 ;
        RECT 418.560 398.605 419.560 398.885 ;
    END
  END dout[623]

  PIN dout[624]
    DIRECTION OUTPUT ;
    USE SIGNAL ;
    PORT
      LAYER met3 ;
        RECT 418.560 399.240 419.560 399.520 ;
    END
  END dout[624]

  PIN dout[625]
    DIRECTION OUTPUT ;
    USE SIGNAL ;
    PORT
      LAYER met3 ;
        RECT 418.560 399.875 419.560 400.155 ;
    END
  END dout[625]

  PIN dout[626]
    DIRECTION OUTPUT ;
    USE SIGNAL ;
    PORT
      LAYER met3 ;
        RECT 418.560 400.510 419.560 400.790 ;
    END
  END dout[626]

  PIN dout[627]
    DIRECTION OUTPUT ;
    USE SIGNAL ;
    PORT
      LAYER met3 ;
        RECT 418.560 401.145 419.560 401.425 ;
    END
  END dout[627]

  PIN dout[628]
    DIRECTION OUTPUT ;
    USE SIGNAL ;
    PORT
      LAYER met3 ;
        RECT 418.560 401.780 419.560 402.060 ;
    END
  END dout[628]

  PIN dout[629]
    DIRECTION OUTPUT ;
    USE SIGNAL ;
    PORT
      LAYER met3 ;
        RECT 418.560 402.415 419.560 402.695 ;
    END
  END dout[629]

  PIN dout[630]
    DIRECTION OUTPUT ;
    USE SIGNAL ;
    PORT
      LAYER met3 ;
        RECT 418.560 403.050 419.560 403.330 ;
    END
  END dout[630]

  PIN dout[631]
    DIRECTION OUTPUT ;
    USE SIGNAL ;
    PORT
      LAYER met3 ;
        RECT 418.560 403.685 419.560 403.965 ;
    END
  END dout[631]

  PIN dout[632]
    DIRECTION OUTPUT ;
    USE SIGNAL ;
    PORT
      LAYER met3 ;
        RECT 418.560 404.320 419.560 404.600 ;
    END
  END dout[632]

  PIN dout[633]
    DIRECTION OUTPUT ;
    USE SIGNAL ;
    PORT
      LAYER met3 ;
        RECT 418.560 404.955 419.560 405.235 ;
    END
  END dout[633]

  PIN dout[634]
    DIRECTION OUTPUT ;
    USE SIGNAL ;
    PORT
      LAYER met3 ;
        RECT 418.560 405.590 419.560 405.870 ;
    END
  END dout[634]

  PIN dout[635]
    DIRECTION OUTPUT ;
    USE SIGNAL ;
    PORT
      LAYER met3 ;
        RECT 418.560 406.225 419.560 406.505 ;
    END
  END dout[635]

  PIN dout[636]
    DIRECTION OUTPUT ;
    USE SIGNAL ;
    PORT
      LAYER met3 ;
        RECT 418.560 406.860 419.560 407.140 ;
    END
  END dout[636]

  PIN dout[637]
    DIRECTION OUTPUT ;
    USE SIGNAL ;
    PORT
      LAYER met3 ;
        RECT 418.560 407.495 419.560 407.775 ;
    END
  END dout[637]

  PIN dout[638]
    DIRECTION OUTPUT ;
    USE SIGNAL ;
    PORT
      LAYER met3 ;
        RECT 418.560 408.130 419.560 408.410 ;
    END
  END dout[638]

  PIN dout[639]
    DIRECTION OUTPUT ;
    USE SIGNAL ;
    PORT
      LAYER met3 ;
        RECT 418.560 408.765 419.560 409.045 ;
    END
  END dout[639]

  PIN dout[640]
    DIRECTION OUTPUT ;
    USE SIGNAL ;
    PORT
      LAYER met3 ;
        RECT 418.560 409.400 419.560 409.680 ;
    END
  END dout[640]

  PIN dout[641]
    DIRECTION OUTPUT ;
    USE SIGNAL ;
    PORT
      LAYER met3 ;
        RECT 418.560 410.035 419.560 410.315 ;
    END
  END dout[641]

  PIN dout[642]
    DIRECTION OUTPUT ;
    USE SIGNAL ;
    PORT
      LAYER met3 ;
        RECT 418.560 410.670 419.560 410.950 ;
    END
  END dout[642]

  PIN dout[643]
    DIRECTION OUTPUT ;
    USE SIGNAL ;
    PORT
      LAYER met3 ;
        RECT 418.560 411.305 419.560 411.585 ;
    END
  END dout[643]

  PIN dout[644]
    DIRECTION OUTPUT ;
    USE SIGNAL ;
    PORT
      LAYER met3 ;
        RECT 418.560 411.940 419.560 412.220 ;
    END
  END dout[644]

  PIN dout[645]
    DIRECTION OUTPUT ;
    USE SIGNAL ;
    PORT
      LAYER met3 ;
        RECT 418.560 412.575 419.560 412.855 ;
    END
  END dout[645]

  PIN dout[646]
    DIRECTION OUTPUT ;
    USE SIGNAL ;
    PORT
      LAYER met3 ;
        RECT 418.560 413.210 419.560 413.490 ;
    END
  END dout[646]

  PIN dout[647]
    DIRECTION OUTPUT ;
    USE SIGNAL ;
    PORT
      LAYER met3 ;
        RECT 418.560 413.845 419.560 414.125 ;
    END
  END dout[647]

  PIN dout[648]
    DIRECTION OUTPUT ;
    USE SIGNAL ;
    PORT
      LAYER met3 ;
        RECT 418.560 414.480 419.560 414.760 ;
    END
  END dout[648]

  PIN dout[649]
    DIRECTION OUTPUT ;
    USE SIGNAL ;
    PORT
      LAYER met3 ;
        RECT 418.560 415.115 419.560 415.395 ;
    END
  END dout[649]

  PIN dout[650]
    DIRECTION OUTPUT ;
    USE SIGNAL ;
    PORT
      LAYER met3 ;
        RECT 418.560 415.750 419.560 416.030 ;
    END
  END dout[650]

  PIN dout[651]
    DIRECTION OUTPUT ;
    USE SIGNAL ;
    PORT
      LAYER met3 ;
        RECT 418.560 416.385 419.560 416.665 ;
    END
  END dout[651]

  PIN dout[652]
    DIRECTION OUTPUT ;
    USE SIGNAL ;
    PORT
      LAYER met3 ;
        RECT 418.560 417.020 419.560 417.300 ;
    END
  END dout[652]

  PIN dout[653]
    DIRECTION OUTPUT ;
    USE SIGNAL ;
    PORT
      LAYER met3 ;
        RECT 418.560 417.655 419.560 417.935 ;
    END
  END dout[653]

  PIN dout[654]
    DIRECTION OUTPUT ;
    USE SIGNAL ;
    PORT
      LAYER met3 ;
        RECT 418.560 418.290 419.560 418.570 ;
    END
  END dout[654]

  PIN dout[655]
    DIRECTION OUTPUT ;
    USE SIGNAL ;
    PORT
      LAYER met3 ;
        RECT 418.560 418.925 419.560 419.205 ;
    END
  END dout[655]

  PIN dout[656]
    DIRECTION OUTPUT ;
    USE SIGNAL ;
    PORT
      LAYER met3 ;
        RECT 418.560 419.560 419.560 419.840 ;
    END
  END dout[656]

  PIN dout[657]
    DIRECTION OUTPUT ;
    USE SIGNAL ;
    PORT
      LAYER met3 ;
        RECT 418.560 420.195 419.560 420.475 ;
    END
  END dout[657]

  PIN dout[658]
    DIRECTION OUTPUT ;
    USE SIGNAL ;
    PORT
      LAYER met3 ;
        RECT 418.560 420.830 419.560 421.110 ;
    END
  END dout[658]

  PIN dout[659]
    DIRECTION OUTPUT ;
    USE SIGNAL ;
    PORT
      LAYER met3 ;
        RECT 418.560 421.465 419.560 421.745 ;
    END
  END dout[659]

  PIN dout[660]
    DIRECTION OUTPUT ;
    USE SIGNAL ;
    PORT
      LAYER met3 ;
        RECT 418.560 422.100 419.560 422.380 ;
    END
  END dout[660]

  PIN dout[661]
    DIRECTION OUTPUT ;
    USE SIGNAL ;
    PORT
      LAYER met3 ;
        RECT 418.560 422.735 419.560 423.015 ;
    END
  END dout[661]

  PIN dout[662]
    DIRECTION OUTPUT ;
    USE SIGNAL ;
    PORT
      LAYER met3 ;
        RECT 418.560 423.370 419.560 423.650 ;
    END
  END dout[662]

  PIN dout[663]
    DIRECTION OUTPUT ;
    USE SIGNAL ;
    PORT
      LAYER met3 ;
        RECT 418.560 424.005 419.560 424.285 ;
    END
  END dout[663]

  PIN dout[664]
    DIRECTION OUTPUT ;
    USE SIGNAL ;
    PORT
      LAYER met3 ;
        RECT 418.560 424.640 419.560 424.920 ;
    END
  END dout[664]

  PIN dout[665]
    DIRECTION OUTPUT ;
    USE SIGNAL ;
    PORT
      LAYER met3 ;
        RECT 418.560 425.275 419.560 425.555 ;
    END
  END dout[665]

  PIN dout[666]
    DIRECTION OUTPUT ;
    USE SIGNAL ;
    PORT
      LAYER met3 ;
        RECT 418.560 425.910 419.560 426.190 ;
    END
  END dout[666]

  PIN dout[667]
    DIRECTION OUTPUT ;
    USE SIGNAL ;
    PORT
      LAYER met3 ;
        RECT 418.560 426.545 419.560 426.825 ;
    END
  END dout[667]

  PIN dout[668]
    DIRECTION OUTPUT ;
    USE SIGNAL ;
    PORT
      LAYER met3 ;
        RECT 418.560 427.180 419.560 427.460 ;
    END
  END dout[668]

  PIN dout[669]
    DIRECTION OUTPUT ;
    USE SIGNAL ;
    PORT
      LAYER met3 ;
        RECT 418.560 427.815 419.560 428.095 ;
    END
  END dout[669]

  PIN dout[670]
    DIRECTION OUTPUT ;
    USE SIGNAL ;
    PORT
      LAYER met3 ;
        RECT 418.560 428.450 419.560 428.730 ;
    END
  END dout[670]

  PIN dout[671]
    DIRECTION OUTPUT ;
    USE SIGNAL ;
    PORT
      LAYER met3 ;
        RECT 418.560 429.085 419.560 429.365 ;
    END
  END dout[671]

  PIN dout[672]
    DIRECTION OUTPUT ;
    USE SIGNAL ;
    PORT
      LAYER met3 ;
        RECT 418.560 429.720 419.560 430.000 ;
    END
  END dout[672]

  PIN dout[673]
    DIRECTION OUTPUT ;
    USE SIGNAL ;
    PORT
      LAYER met3 ;
        RECT 418.560 430.355 419.560 430.635 ;
    END
  END dout[673]

  PIN dout[674]
    DIRECTION OUTPUT ;
    USE SIGNAL ;
    PORT
      LAYER met3 ;
        RECT 418.560 430.990 419.560 431.270 ;
    END
  END dout[674]

  PIN dout[675]
    DIRECTION OUTPUT ;
    USE SIGNAL ;
    PORT
      LAYER met3 ;
        RECT 418.560 431.625 419.560 431.905 ;
    END
  END dout[675]

  PIN dout[676]
    DIRECTION OUTPUT ;
    USE SIGNAL ;
    PORT
      LAYER met3 ;
        RECT 418.560 432.260 419.560 432.540 ;
    END
  END dout[676]

  PIN dout[677]
    DIRECTION OUTPUT ;
    USE SIGNAL ;
    PORT
      LAYER met3 ;
        RECT 418.560 432.895 419.560 433.175 ;
    END
  END dout[677]

  PIN dout[678]
    DIRECTION OUTPUT ;
    USE SIGNAL ;
    PORT
      LAYER met3 ;
        RECT 418.560 433.530 419.560 433.810 ;
    END
  END dout[678]

  PIN dout[679]
    DIRECTION OUTPUT ;
    USE SIGNAL ;
    PORT
      LAYER met3 ;
        RECT 418.560 434.165 419.560 434.445 ;
    END
  END dout[679]

  PIN dout[680]
    DIRECTION OUTPUT ;
    USE SIGNAL ;
    PORT
      LAYER met3 ;
        RECT 418.560 434.800 419.560 435.080 ;
    END
  END dout[680]

  PIN dout[681]
    DIRECTION OUTPUT ;
    USE SIGNAL ;
    PORT
      LAYER met3 ;
        RECT 418.560 435.435 419.560 435.715 ;
    END
  END dout[681]

  PIN dout[682]
    DIRECTION OUTPUT ;
    USE SIGNAL ;
    PORT
      LAYER met3 ;
        RECT 418.560 436.070 419.560 436.350 ;
    END
  END dout[682]

  PIN dout[683]
    DIRECTION OUTPUT ;
    USE SIGNAL ;
    PORT
      LAYER met3 ;
        RECT 418.560 436.705 419.560 436.985 ;
    END
  END dout[683]

  PIN dout[684]
    DIRECTION OUTPUT ;
    USE SIGNAL ;
    PORT
      LAYER met3 ;
        RECT 418.560 437.340 419.560 437.620 ;
    END
  END dout[684]

  PIN dout[685]
    DIRECTION OUTPUT ;
    USE SIGNAL ;
    PORT
      LAYER met3 ;
        RECT 418.560 437.975 419.560 438.255 ;
    END
  END dout[685]

  PIN dout[686]
    DIRECTION OUTPUT ;
    USE SIGNAL ;
    PORT
      LAYER met3 ;
        RECT 418.560 438.610 419.560 438.890 ;
    END
  END dout[686]

  PIN dout[687]
    DIRECTION OUTPUT ;
    USE SIGNAL ;
    PORT
      LAYER met3 ;
        RECT 418.560 439.245 419.560 439.525 ;
    END
  END dout[687]

  PIN dout[688]
    DIRECTION OUTPUT ;
    USE SIGNAL ;
    PORT
      LAYER met3 ;
        RECT 418.560 439.880 419.560 440.160 ;
    END
  END dout[688]

  PIN dout[689]
    DIRECTION OUTPUT ;
    USE SIGNAL ;
    PORT
      LAYER met3 ;
        RECT 418.560 440.515 419.560 440.795 ;
    END
  END dout[689]

  PIN dout[690]
    DIRECTION OUTPUT ;
    USE SIGNAL ;
    PORT
      LAYER met3 ;
        RECT 418.560 441.150 419.560 441.430 ;
    END
  END dout[690]

  PIN dout[691]
    DIRECTION OUTPUT ;
    USE SIGNAL ;
    PORT
      LAYER met3 ;
        RECT 418.560 441.785 419.560 442.065 ;
    END
  END dout[691]

  PIN dout[692]
    DIRECTION OUTPUT ;
    USE SIGNAL ;
    PORT
      LAYER met3 ;
        RECT 418.560 442.420 419.560 442.700 ;
    END
  END dout[692]

  PIN dout[693]
    DIRECTION OUTPUT ;
    USE SIGNAL ;
    PORT
      LAYER met3 ;
        RECT 418.560 443.055 419.560 443.335 ;
    END
  END dout[693]

  PIN dout[694]
    DIRECTION OUTPUT ;
    USE SIGNAL ;
    PORT
      LAYER met3 ;
        RECT 418.560 443.690 419.560 443.970 ;
    END
  END dout[694]

  PIN dout[695]
    DIRECTION OUTPUT ;
    USE SIGNAL ;
    PORT
      LAYER met3 ;
        RECT 418.560 444.325 419.560 444.605 ;
    END
  END dout[695]

  PIN dout[696]
    DIRECTION OUTPUT ;
    USE SIGNAL ;
    PORT
      LAYER met3 ;
        RECT 418.560 444.960 419.560 445.240 ;
    END
  END dout[696]

  PIN dout[697]
    DIRECTION OUTPUT ;
    USE SIGNAL ;
    PORT
      LAYER met3 ;
        RECT 418.560 445.595 419.560 445.875 ;
    END
  END dout[697]

  PIN dout[698]
    DIRECTION OUTPUT ;
    USE SIGNAL ;
    PORT
      LAYER met3 ;
        RECT 418.560 446.230 419.560 446.510 ;
    END
  END dout[698]

  PIN dout[699]
    DIRECTION OUTPUT ;
    USE SIGNAL ;
    PORT
      LAYER met3 ;
        RECT 418.560 446.865 419.560 447.145 ;
    END
  END dout[699]

  PIN dout[700]
    DIRECTION OUTPUT ;
    USE SIGNAL ;
    PORT
      LAYER met3 ;
        RECT 418.560 447.500 419.560 447.780 ;
    END
  END dout[700]

  PIN dout[701]
    DIRECTION OUTPUT ;
    USE SIGNAL ;
    PORT
      LAYER met3 ;
        RECT 418.560 448.135 419.560 448.415 ;
    END
  END dout[701]

  PIN dout[702]
    DIRECTION OUTPUT ;
    USE SIGNAL ;
    PORT
      LAYER met3 ;
        RECT 418.560 448.770 419.560 449.050 ;
    END
  END dout[702]

  PIN dout[703]
    DIRECTION OUTPUT ;
    USE SIGNAL ;
    PORT
      LAYER met3 ;
        RECT 418.560 449.405 419.560 449.685 ;
    END
  END dout[703]

  PIN dout[704]
    DIRECTION OUTPUT ;
    USE SIGNAL ;
    PORT
      LAYER met3 ;
        RECT 418.560 450.040 419.560 450.320 ;
    END
  END dout[704]

  PIN dout[705]
    DIRECTION OUTPUT ;
    USE SIGNAL ;
    PORT
      LAYER met3 ;
        RECT 418.560 450.675 419.560 450.955 ;
    END
  END dout[705]

  PIN dout[706]
    DIRECTION OUTPUT ;
    USE SIGNAL ;
    PORT
      LAYER met3 ;
        RECT 418.560 451.310 419.560 451.590 ;
    END
  END dout[706]

  PIN dout[707]
    DIRECTION OUTPUT ;
    USE SIGNAL ;
    PORT
      LAYER met3 ;
        RECT 418.560 451.945 419.560 452.225 ;
    END
  END dout[707]

  PIN dout[708]
    DIRECTION OUTPUT ;
    USE SIGNAL ;
    PORT
      LAYER met3 ;
        RECT 418.560 452.580 419.560 452.860 ;
    END
  END dout[708]

  PIN dout[709]
    DIRECTION OUTPUT ;
    USE SIGNAL ;
    PORT
      LAYER met3 ;
        RECT 418.560 453.215 419.560 453.495 ;
    END
  END dout[709]

  PIN dout[710]
    DIRECTION OUTPUT ;
    USE SIGNAL ;
    PORT
      LAYER met3 ;
        RECT 418.560 453.850 419.560 454.130 ;
    END
  END dout[710]

  PIN dout[711]
    DIRECTION OUTPUT ;
    USE SIGNAL ;
    PORT
      LAYER met3 ;
        RECT 418.560 454.485 419.560 454.765 ;
    END
  END dout[711]

  PIN dout[712]
    DIRECTION OUTPUT ;
    USE SIGNAL ;
    PORT
      LAYER met3 ;
        RECT 418.560 455.120 419.560 455.400 ;
    END
  END dout[712]

  PIN dout[713]
    DIRECTION OUTPUT ;
    USE SIGNAL ;
    PORT
      LAYER met3 ;
        RECT 418.560 455.755 419.560 456.035 ;
    END
  END dout[713]

  PIN dout[714]
    DIRECTION OUTPUT ;
    USE SIGNAL ;
    PORT
      LAYER met3 ;
        RECT 418.560 456.390 419.560 456.670 ;
    END
  END dout[714]

  PIN dout[715]
    DIRECTION OUTPUT ;
    USE SIGNAL ;
    PORT
      LAYER met3 ;
        RECT 418.560 457.025 419.560 457.305 ;
    END
  END dout[715]

  PIN dout[716]
    DIRECTION OUTPUT ;
    USE SIGNAL ;
    PORT
      LAYER met3 ;
        RECT 418.560 457.660 419.560 457.940 ;
    END
  END dout[716]

  PIN dout[717]
    DIRECTION OUTPUT ;
    USE SIGNAL ;
    PORT
      LAYER met3 ;
        RECT 418.560 458.295 419.560 458.575 ;
    END
  END dout[717]

  PIN dout[718]
    DIRECTION OUTPUT ;
    USE SIGNAL ;
    PORT
      LAYER met3 ;
        RECT 418.560 458.930 419.560 459.210 ;
    END
  END dout[718]

  PIN dout[719]
    DIRECTION OUTPUT ;
    USE SIGNAL ;
    PORT
      LAYER met3 ;
        RECT 418.560 459.565 419.560 459.845 ;
    END
  END dout[719]

  PIN dout[720]
    DIRECTION OUTPUT ;
    USE SIGNAL ;
    PORT
      LAYER met3 ;
        RECT 418.560 460.200 419.560 460.480 ;
    END
  END dout[720]

  PIN dout[721]
    DIRECTION OUTPUT ;
    USE SIGNAL ;
    PORT
      LAYER met3 ;
        RECT 418.560 460.835 419.560 461.115 ;
    END
  END dout[721]

  PIN dout[722]
    DIRECTION OUTPUT ;
    USE SIGNAL ;
    PORT
      LAYER met3 ;
        RECT 418.560 461.470 419.560 461.750 ;
    END
  END dout[722]

  PIN dout[723]
    DIRECTION OUTPUT ;
    USE SIGNAL ;
    PORT
      LAYER met3 ;
        RECT 418.560 462.105 419.560 462.385 ;
    END
  END dout[723]

  PIN dout[724]
    DIRECTION OUTPUT ;
    USE SIGNAL ;
    PORT
      LAYER met3 ;
        RECT 418.560 462.740 419.560 463.020 ;
    END
  END dout[724]

  PIN dout[725]
    DIRECTION OUTPUT ;
    USE SIGNAL ;
    PORT
      LAYER met3 ;
        RECT 418.560 463.375 419.560 463.655 ;
    END
  END dout[725]

  PIN dout[726]
    DIRECTION OUTPUT ;
    USE SIGNAL ;
    PORT
      LAYER met3 ;
        RECT 418.560 464.010 419.560 464.290 ;
    END
  END dout[726]

  PIN dout[727]
    DIRECTION OUTPUT ;
    USE SIGNAL ;
    PORT
      LAYER met3 ;
        RECT 418.560 464.645 419.560 464.925 ;
    END
  END dout[727]

  PIN dout[728]
    DIRECTION OUTPUT ;
    USE SIGNAL ;
    PORT
      LAYER met3 ;
        RECT 418.560 465.280 419.560 465.560 ;
    END
  END dout[728]

  PIN dout[729]
    DIRECTION OUTPUT ;
    USE SIGNAL ;
    PORT
      LAYER met3 ;
        RECT 418.560 465.915 419.560 466.195 ;
    END
  END dout[729]

  PIN dout[730]
    DIRECTION OUTPUT ;
    USE SIGNAL ;
    PORT
      LAYER met3 ;
        RECT 418.560 466.550 419.560 466.830 ;
    END
  END dout[730]

  PIN dout[731]
    DIRECTION OUTPUT ;
    USE SIGNAL ;
    PORT
      LAYER met3 ;
        RECT 418.560 467.185 419.560 467.465 ;
    END
  END dout[731]

  PIN dout[732]
    DIRECTION OUTPUT ;
    USE SIGNAL ;
    PORT
      LAYER met3 ;
        RECT 418.560 467.820 419.560 468.100 ;
    END
  END dout[732]

  PIN dout[733]
    DIRECTION OUTPUT ;
    USE SIGNAL ;
    PORT
      LAYER met3 ;
        RECT 418.560 468.455 419.560 468.735 ;
    END
  END dout[733]

  PIN dout[734]
    DIRECTION OUTPUT ;
    USE SIGNAL ;
    PORT
      LAYER met3 ;
        RECT 418.560 469.090 419.560 469.370 ;
    END
  END dout[734]

  PIN dout[735]
    DIRECTION OUTPUT ;
    USE SIGNAL ;
    PORT
      LAYER met3 ;
        RECT 418.560 469.725 419.560 470.005 ;
    END
  END dout[735]

  PIN dout[736]
    DIRECTION OUTPUT ;
    USE SIGNAL ;
    PORT
      LAYER met3 ;
        RECT 418.560 470.360 419.560 470.640 ;
    END
  END dout[736]

  PIN dout[737]
    DIRECTION OUTPUT ;
    USE SIGNAL ;
    PORT
      LAYER met3 ;
        RECT 418.560 470.995 419.560 471.275 ;
    END
  END dout[737]

  PIN dout[738]
    DIRECTION OUTPUT ;
    USE SIGNAL ;
    PORT
      LAYER met3 ;
        RECT 418.560 471.630 419.560 471.910 ;
    END
  END dout[738]

  PIN dout[739]
    DIRECTION OUTPUT ;
    USE SIGNAL ;
    PORT
      LAYER met3 ;
        RECT 418.560 472.265 419.560 472.545 ;
    END
  END dout[739]

  PIN dout[740]
    DIRECTION OUTPUT ;
    USE SIGNAL ;
    PORT
      LAYER met3 ;
        RECT 418.560 472.900 419.560 473.180 ;
    END
  END dout[740]

  PIN dout[741]
    DIRECTION OUTPUT ;
    USE SIGNAL ;
    PORT
      LAYER met3 ;
        RECT 418.560 473.535 419.560 473.815 ;
    END
  END dout[741]

  PIN dout[742]
    DIRECTION OUTPUT ;
    USE SIGNAL ;
    PORT
      LAYER met3 ;
        RECT 418.560 474.170 419.560 474.450 ;
    END
  END dout[742]

  PIN dout[743]
    DIRECTION OUTPUT ;
    USE SIGNAL ;
    PORT
      LAYER met3 ;
        RECT 418.560 474.805 419.560 475.085 ;
    END
  END dout[743]

  PIN dout[744]
    DIRECTION OUTPUT ;
    USE SIGNAL ;
    PORT
      LAYER met3 ;
        RECT 418.560 475.440 419.560 475.720 ;
    END
  END dout[744]

  PIN dout[745]
    DIRECTION OUTPUT ;
    USE SIGNAL ;
    PORT
      LAYER met3 ;
        RECT 418.560 476.075 419.560 476.355 ;
    END
  END dout[745]

  PIN dout[746]
    DIRECTION OUTPUT ;
    USE SIGNAL ;
    PORT
      LAYER met3 ;
        RECT 418.560 476.710 419.560 476.990 ;
    END
  END dout[746]

  PIN dout[747]
    DIRECTION OUTPUT ;
    USE SIGNAL ;
    PORT
      LAYER met3 ;
        RECT 418.560 477.345 419.560 477.625 ;
    END
  END dout[747]

  PIN dout[748]
    DIRECTION OUTPUT ;
    USE SIGNAL ;
    PORT
      LAYER met3 ;
        RECT 418.560 477.980 419.560 478.260 ;
    END
  END dout[748]

  PIN dout[749]
    DIRECTION OUTPUT ;
    USE SIGNAL ;
    PORT
      LAYER met3 ;
        RECT 418.560 478.615 419.560 478.895 ;
    END
  END dout[749]

  PIN dout[750]
    DIRECTION OUTPUT ;
    USE SIGNAL ;
    PORT
      LAYER met3 ;
        RECT 418.560 479.250 419.560 479.530 ;
    END
  END dout[750]

  PIN dout[751]
    DIRECTION OUTPUT ;
    USE SIGNAL ;
    PORT
      LAYER met3 ;
        RECT 418.560 479.885 419.560 480.165 ;
    END
  END dout[751]

  PIN dout[752]
    DIRECTION OUTPUT ;
    USE SIGNAL ;
    PORT
      LAYER met3 ;
        RECT 418.560 480.520 419.560 480.800 ;
    END
  END dout[752]

  PIN dout[753]
    DIRECTION OUTPUT ;
    USE SIGNAL ;
    PORT
      LAYER met3 ;
        RECT 418.560 481.155 419.560 481.435 ;
    END
  END dout[753]

  PIN dout[754]
    DIRECTION OUTPUT ;
    USE SIGNAL ;
    PORT
      LAYER met3 ;
        RECT 418.560 481.790 419.560 482.070 ;
    END
  END dout[754]

  PIN dout[755]
    DIRECTION OUTPUT ;
    USE SIGNAL ;
    PORT
      LAYER met3 ;
        RECT 418.560 482.425 419.560 482.705 ;
    END
  END dout[755]

  PIN dout[756]
    DIRECTION OUTPUT ;
    USE SIGNAL ;
    PORT
      LAYER met3 ;
        RECT 418.560 483.060 419.560 483.340 ;
    END
  END dout[756]

  PIN dout[757]
    DIRECTION OUTPUT ;
    USE SIGNAL ;
    PORT
      LAYER met3 ;
        RECT 418.560 483.695 419.560 483.975 ;
    END
  END dout[757]

  PIN dout[758]
    DIRECTION OUTPUT ;
    USE SIGNAL ;
    PORT
      LAYER met3 ;
        RECT 418.560 484.330 419.560 484.610 ;
    END
  END dout[758]

  PIN dout[759]
    DIRECTION OUTPUT ;
    USE SIGNAL ;
    PORT
      LAYER met3 ;
        RECT 418.560 484.965 419.560 485.245 ;
    END
  END dout[759]

  PIN dout[760]
    DIRECTION OUTPUT ;
    USE SIGNAL ;
    PORT
      LAYER met3 ;
        RECT 418.560 485.600 419.560 485.880 ;
    END
  END dout[760]

  PIN dout[761]
    DIRECTION OUTPUT ;
    USE SIGNAL ;
    PORT
      LAYER met3 ;
        RECT 418.560 486.235 419.560 486.515 ;
    END
  END dout[761]

  PIN dout[762]
    DIRECTION OUTPUT ;
    USE SIGNAL ;
    PORT
      LAYER met3 ;
        RECT 418.560 486.870 419.560 487.150 ;
    END
  END dout[762]

  PIN dout[763]
    DIRECTION OUTPUT ;
    USE SIGNAL ;
    PORT
      LAYER met3 ;
        RECT 418.560 487.505 419.560 487.785 ;
    END
  END dout[763]

  PIN dout[764]
    DIRECTION OUTPUT ;
    USE SIGNAL ;
    PORT
      LAYER met3 ;
        RECT 418.560 488.140 419.560 488.420 ;
    END
  END dout[764]

  PIN dout[765]
    DIRECTION OUTPUT ;
    USE SIGNAL ;
    PORT
      LAYER met3 ;
        RECT 418.560 488.775 419.560 489.055 ;
    END
  END dout[765]

  PIN dout[766]
    DIRECTION OUTPUT ;
    USE SIGNAL ;
    PORT
      LAYER met3 ;
        RECT 418.560 489.410 419.560 489.690 ;
    END
  END dout[766]

  PIN dout[767]
    DIRECTION OUTPUT ;
    USE SIGNAL ;
    PORT
      LAYER met3 ;
        RECT 418.560 490.045 419.560 490.325 ;
    END
  END dout[767]

  PIN dout[768]
    DIRECTION OUTPUT ;
    USE SIGNAL ;
    PORT
      LAYER met3 ;
        RECT 418.560 490.680 419.560 490.960 ;
    END
  END dout[768]

  PIN dout[769]
    DIRECTION OUTPUT ;
    USE SIGNAL ;
    PORT
      LAYER met3 ;
        RECT 418.560 491.315 419.560 491.595 ;
    END
  END dout[769]

  PIN dout[770]
    DIRECTION OUTPUT ;
    USE SIGNAL ;
    PORT
      LAYER met3 ;
        RECT 418.560 491.950 419.560 492.230 ;
    END
  END dout[770]

  PIN dout[771]
    DIRECTION OUTPUT ;
    USE SIGNAL ;
    PORT
      LAYER met3 ;
        RECT 418.560 492.585 419.560 492.865 ;
    END
  END dout[771]

  PIN dout[772]
    DIRECTION OUTPUT ;
    USE SIGNAL ;
    PORT
      LAYER met3 ;
        RECT 418.560 493.220 419.560 493.500 ;
    END
  END dout[772]

  PIN dout[773]
    DIRECTION OUTPUT ;
    USE SIGNAL ;
    PORT
      LAYER met3 ;
        RECT 418.560 493.855 419.560 494.135 ;
    END
  END dout[773]

  PIN dout[774]
    DIRECTION OUTPUT ;
    USE SIGNAL ;
    PORT
      LAYER met3 ;
        RECT 418.560 494.490 419.560 494.770 ;
    END
  END dout[774]

  PIN dout[775]
    DIRECTION OUTPUT ;
    USE SIGNAL ;
    PORT
      LAYER met3 ;
        RECT 418.560 495.125 419.560 495.405 ;
    END
  END dout[775]

  PIN dout[776]
    DIRECTION OUTPUT ;
    USE SIGNAL ;
    PORT
      LAYER met3 ;
        RECT 418.560 495.760 419.560 496.040 ;
    END
  END dout[776]

  PIN dout[777]
    DIRECTION OUTPUT ;
    USE SIGNAL ;
    PORT
      LAYER met3 ;
        RECT 418.560 496.395 419.560 496.675 ;
    END
  END dout[777]

  PIN dout[778]
    DIRECTION OUTPUT ;
    USE SIGNAL ;
    PORT
      LAYER met3 ;
        RECT 418.560 497.030 419.560 497.310 ;
    END
  END dout[778]

  PIN dout[779]
    DIRECTION OUTPUT ;
    USE SIGNAL ;
    PORT
      LAYER met3 ;
        RECT 418.560 497.665 419.560 497.945 ;
    END
  END dout[779]

  PIN dout[780]
    DIRECTION OUTPUT ;
    USE SIGNAL ;
    PORT
      LAYER met3 ;
        RECT 418.560 498.300 419.560 498.580 ;
    END
  END dout[780]

  PIN dout[781]
    DIRECTION OUTPUT ;
    USE SIGNAL ;
    PORT
      LAYER met3 ;
        RECT 418.560 498.935 419.560 499.215 ;
    END
  END dout[781]

  PIN dout[782]
    DIRECTION OUTPUT ;
    USE SIGNAL ;
    PORT
      LAYER met3 ;
        RECT 418.560 499.570 419.560 499.850 ;
    END
  END dout[782]

  PIN dout[783]
    DIRECTION OUTPUT ;
    USE SIGNAL ;
    PORT
      LAYER met3 ;
        RECT 418.560 500.205 419.560 500.485 ;
    END
  END dout[783]

  PIN dout[784]
    DIRECTION OUTPUT ;
    USE SIGNAL ;
    PORT
      LAYER met3 ;
        RECT 418.560 500.840 419.560 501.120 ;
    END
  END dout[784]

  PIN dout[785]
    DIRECTION OUTPUT ;
    USE SIGNAL ;
    PORT
      LAYER met3 ;
        RECT 418.560 501.475 419.560 501.755 ;
    END
  END dout[785]

  PIN dout[786]
    DIRECTION OUTPUT ;
    USE SIGNAL ;
    PORT
      LAYER met3 ;
        RECT 418.560 502.110 419.560 502.390 ;
    END
  END dout[786]

  PIN dout[787]
    DIRECTION OUTPUT ;
    USE SIGNAL ;
    PORT
      LAYER met3 ;
        RECT 418.560 502.745 419.560 503.025 ;
    END
  END dout[787]

  PIN dout[788]
    DIRECTION OUTPUT ;
    USE SIGNAL ;
    PORT
      LAYER met3 ;
        RECT 418.560 503.380 419.560 503.660 ;
    END
  END dout[788]

  PIN dout[789]
    DIRECTION OUTPUT ;
    USE SIGNAL ;
    PORT
      LAYER met3 ;
        RECT 418.560 504.015 419.560 504.295 ;
    END
  END dout[789]

  PIN dout[790]
    DIRECTION OUTPUT ;
    USE SIGNAL ;
    PORT
      LAYER met3 ;
        RECT 418.560 504.650 419.560 504.930 ;
    END
  END dout[790]

  PIN dout[791]
    DIRECTION OUTPUT ;
    USE SIGNAL ;
    PORT
      LAYER met3 ;
        RECT 418.560 505.285 419.560 505.565 ;
    END
  END dout[791]

  PIN dout[792]
    DIRECTION OUTPUT ;
    USE SIGNAL ;
    PORT
      LAYER met3 ;
        RECT 418.560 505.920 419.560 506.200 ;
    END
  END dout[792]

  PIN dout[793]
    DIRECTION OUTPUT ;
    USE SIGNAL ;
    PORT
      LAYER met3 ;
        RECT 418.560 506.555 419.560 506.835 ;
    END
  END dout[793]

  PIN dout[794]
    DIRECTION OUTPUT ;
    USE SIGNAL ;
    PORT
      LAYER met3 ;
        RECT 418.560 507.190 419.560 507.470 ;
    END
  END dout[794]

  PIN dout[795]
    DIRECTION OUTPUT ;
    USE SIGNAL ;
    PORT
      LAYER met3 ;
        RECT 418.560 507.825 419.560 508.105 ;
    END
  END dout[795]

  PIN dout[796]
    DIRECTION OUTPUT ;
    USE SIGNAL ;
    PORT
      LAYER met3 ;
        RECT 418.560 508.460 419.560 508.740 ;
    END
  END dout[796]

  PIN dout[797]
    DIRECTION OUTPUT ;
    USE SIGNAL ;
    PORT
      LAYER met3 ;
        RECT 418.560 509.095 419.560 509.375 ;
    END
  END dout[797]

  PIN dout[798]
    DIRECTION OUTPUT ;
    USE SIGNAL ;
    PORT
      LAYER met3 ;
        RECT 418.560 509.730 419.560 510.010 ;
    END
  END dout[798]

  PIN dout[799]
    DIRECTION OUTPUT ;
    USE SIGNAL ;
    PORT
      LAYER met3 ;
        RECT 418.560 510.365 419.560 510.645 ;
    END
  END dout[799]

  PIN dout[800]
    DIRECTION OUTPUT ;
    USE SIGNAL ;
    PORT
      LAYER met3 ;
        RECT 418.560 511.000 419.560 511.280 ;
    END
  END dout[800]

  PIN dout[801]
    DIRECTION OUTPUT ;
    USE SIGNAL ;
    PORT
      LAYER met3 ;
        RECT 418.560 511.635 419.560 511.915 ;
    END
  END dout[801]

  PIN dout[802]
    DIRECTION OUTPUT ;
    USE SIGNAL ;
    PORT
      LAYER met3 ;
        RECT 418.560 512.270 419.560 512.550 ;
    END
  END dout[802]

  PIN dout[803]
    DIRECTION OUTPUT ;
    USE SIGNAL ;
    PORT
      LAYER met3 ;
        RECT 418.560 512.905 419.560 513.185 ;
    END
  END dout[803]

  PIN dout[804]
    DIRECTION OUTPUT ;
    USE SIGNAL ;
    PORT
      LAYER met3 ;
        RECT 418.560 513.540 419.560 513.820 ;
    END
  END dout[804]

  PIN dout[805]
    DIRECTION OUTPUT ;
    USE SIGNAL ;
    PORT
      LAYER met3 ;
        RECT 418.560 514.175 419.560 514.455 ;
    END
  END dout[805]

  PIN dout[806]
    DIRECTION OUTPUT ;
    USE SIGNAL ;
    PORT
      LAYER met3 ;
        RECT 418.560 514.810 419.560 515.090 ;
    END
  END dout[806]

  PIN dout[807]
    DIRECTION OUTPUT ;
    USE SIGNAL ;
    PORT
      LAYER met3 ;
        RECT 418.560 515.445 419.560 515.725 ;
    END
  END dout[807]

  PIN dout[808]
    DIRECTION OUTPUT ;
    USE SIGNAL ;
    PORT
      LAYER met3 ;
        RECT 418.560 516.080 419.560 516.360 ;
    END
  END dout[808]

  PIN dout[809]
    DIRECTION OUTPUT ;
    USE SIGNAL ;
    PORT
      LAYER met3 ;
        RECT 418.560 516.715 419.560 516.995 ;
    END
  END dout[809]

  PIN dout[810]
    DIRECTION OUTPUT ;
    USE SIGNAL ;
    PORT
      LAYER met3 ;
        RECT 418.560 517.350 419.560 517.630 ;
    END
  END dout[810]

  PIN dout[811]
    DIRECTION OUTPUT ;
    USE SIGNAL ;
    PORT
      LAYER met3 ;
        RECT 418.560 517.985 419.560 518.265 ;
    END
  END dout[811]

  PIN dout[812]
    DIRECTION OUTPUT ;
    USE SIGNAL ;
    PORT
      LAYER met3 ;
        RECT 418.560 518.620 419.560 518.900 ;
    END
  END dout[812]

  PIN dout[813]
    DIRECTION OUTPUT ;
    USE SIGNAL ;
    PORT
      LAYER met3 ;
        RECT 418.560 519.255 419.560 519.535 ;
    END
  END dout[813]

  PIN dout[814]
    DIRECTION OUTPUT ;
    USE SIGNAL ;
    PORT
      LAYER met3 ;
        RECT 418.560 519.890 419.560 520.170 ;
    END
  END dout[814]

  PIN dout[815]
    DIRECTION OUTPUT ;
    USE SIGNAL ;
    PORT
      LAYER met3 ;
        RECT 418.560 520.525 419.560 520.805 ;
    END
  END dout[815]

  PIN dout[816]
    DIRECTION OUTPUT ;
    USE SIGNAL ;
    PORT
      LAYER met3 ;
        RECT 418.560 521.160 419.560 521.440 ;
    END
  END dout[816]

  PIN dout[817]
    DIRECTION OUTPUT ;
    USE SIGNAL ;
    PORT
      LAYER met3 ;
        RECT 418.560 521.795 419.560 522.075 ;
    END
  END dout[817]

  PIN dout[818]
    DIRECTION OUTPUT ;
    USE SIGNAL ;
    PORT
      LAYER met3 ;
        RECT 418.560 522.430 419.560 522.710 ;
    END
  END dout[818]

  PIN dout[819]
    DIRECTION OUTPUT ;
    USE SIGNAL ;
    PORT
      LAYER met3 ;
        RECT 418.560 523.065 419.560 523.345 ;
    END
  END dout[819]

  PIN dout[820]
    DIRECTION OUTPUT ;
    USE SIGNAL ;
    PORT
      LAYER met3 ;
        RECT 418.560 523.700 419.560 523.980 ;
    END
  END dout[820]

  PIN dout[821]
    DIRECTION OUTPUT ;
    USE SIGNAL ;
    PORT
      LAYER met3 ;
        RECT 418.560 524.335 419.560 524.615 ;
    END
  END dout[821]

  PIN dout[822]
    DIRECTION OUTPUT ;
    USE SIGNAL ;
    PORT
      LAYER met3 ;
        RECT 418.560 524.970 419.560 525.250 ;
    END
  END dout[822]

  PIN dout[823]
    DIRECTION OUTPUT ;
    USE SIGNAL ;
    PORT
      LAYER met3 ;
        RECT 418.560 525.605 419.560 525.885 ;
    END
  END dout[823]

  PIN dout[824]
    DIRECTION OUTPUT ;
    USE SIGNAL ;
    PORT
      LAYER met3 ;
        RECT 418.560 526.240 419.560 526.520 ;
    END
  END dout[824]

  PIN dout[825]
    DIRECTION OUTPUT ;
    USE SIGNAL ;
    PORT
      LAYER met3 ;
        RECT 418.560 526.875 419.560 527.155 ;
    END
  END dout[825]

  PIN dout[826]
    DIRECTION OUTPUT ;
    USE SIGNAL ;
    PORT
      LAYER met3 ;
        RECT 418.560 527.510 419.560 527.790 ;
    END
  END dout[826]

  PIN dout[827]
    DIRECTION OUTPUT ;
    USE SIGNAL ;
    PORT
      LAYER met3 ;
        RECT 418.560 528.145 419.560 528.425 ;
    END
  END dout[827]

  PIN dout[828]
    DIRECTION OUTPUT ;
    USE SIGNAL ;
    PORT
      LAYER met3 ;
        RECT 418.560 528.780 419.560 529.060 ;
    END
  END dout[828]

  PIN dout[829]
    DIRECTION OUTPUT ;
    USE SIGNAL ;
    PORT
      LAYER met3 ;
        RECT 418.560 529.415 419.560 529.695 ;
    END
  END dout[829]

  PIN dout[830]
    DIRECTION OUTPUT ;
    USE SIGNAL ;
    PORT
      LAYER met3 ;
        RECT 418.560 530.050 419.560 530.330 ;
    END
  END dout[830]

  PIN dout[831]
    DIRECTION OUTPUT ;
    USE SIGNAL ;
    PORT
      LAYER met3 ;
        RECT 418.560 530.685 419.560 530.965 ;
    END
  END dout[831]

  PIN dout[832]
    DIRECTION OUTPUT ;
    USE SIGNAL ;
    PORT
      LAYER met3 ;
        RECT 418.560 531.320 419.560 531.600 ;
    END
  END dout[832]

  PIN dout[833]
    DIRECTION OUTPUT ;
    USE SIGNAL ;
    PORT
      LAYER met3 ;
        RECT 418.560 531.955 419.560 532.235 ;
    END
  END dout[833]

  PIN dout[834]
    DIRECTION OUTPUT ;
    USE SIGNAL ;
    PORT
      LAYER met3 ;
        RECT 418.560 532.590 419.560 532.870 ;
    END
  END dout[834]

  PIN dout[835]
    DIRECTION OUTPUT ;
    USE SIGNAL ;
    PORT
      LAYER met3 ;
        RECT 418.560 533.225 419.560 533.505 ;
    END
  END dout[835]

  PIN dout[836]
    DIRECTION OUTPUT ;
    USE SIGNAL ;
    PORT
      LAYER met3 ;
        RECT 418.560 533.860 419.560 534.140 ;
    END
  END dout[836]

  PIN dout[837]
    DIRECTION OUTPUT ;
    USE SIGNAL ;
    PORT
      LAYER met3 ;
        RECT 418.560 534.495 419.560 534.775 ;
    END
  END dout[837]

  PIN dout[838]
    DIRECTION OUTPUT ;
    USE SIGNAL ;
    PORT
      LAYER met3 ;
        RECT 418.560 535.130 419.560 535.410 ;
    END
  END dout[838]

  PIN dout[839]
    DIRECTION OUTPUT ;
    USE SIGNAL ;
    PORT
      LAYER met3 ;
        RECT 418.560 535.765 419.560 536.045 ;
    END
  END dout[839]

  PIN dout[840]
    DIRECTION OUTPUT ;
    USE SIGNAL ;
    PORT
      LAYER met3 ;
        RECT 418.560 536.400 419.560 536.680 ;
    END
  END dout[840]

  PIN dout[841]
    DIRECTION OUTPUT ;
    USE SIGNAL ;
    PORT
      LAYER met3 ;
        RECT 418.560 537.035 419.560 537.315 ;
    END
  END dout[841]

  PIN dout[842]
    DIRECTION OUTPUT ;
    USE SIGNAL ;
    PORT
      LAYER met3 ;
        RECT 418.560 537.670 419.560 537.950 ;
    END
  END dout[842]

  PIN dout[843]
    DIRECTION OUTPUT ;
    USE SIGNAL ;
    PORT
      LAYER met3 ;
        RECT 418.560 538.305 419.560 538.585 ;
    END
  END dout[843]

  PIN dout[844]
    DIRECTION OUTPUT ;
    USE SIGNAL ;
    PORT
      LAYER met3 ;
        RECT 418.560 538.940 419.560 539.220 ;
    END
  END dout[844]

  PIN dout[845]
    DIRECTION OUTPUT ;
    USE SIGNAL ;
    PORT
      LAYER met3 ;
        RECT 418.560 539.575 419.560 539.855 ;
    END
  END dout[845]

  PIN dout[846]
    DIRECTION OUTPUT ;
    USE SIGNAL ;
    PORT
      LAYER met3 ;
        RECT 418.560 540.210 419.560 540.490 ;
    END
  END dout[846]

  PIN dout[847]
    DIRECTION OUTPUT ;
    USE SIGNAL ;
    PORT
      LAYER met3 ;
        RECT 418.560 540.845 419.560 541.125 ;
    END
  END dout[847]

  PIN dout[848]
    DIRECTION OUTPUT ;
    USE SIGNAL ;
    PORT
      LAYER met3 ;
        RECT 418.560 541.480 419.560 541.760 ;
    END
  END dout[848]

  PIN dout[849]
    DIRECTION OUTPUT ;
    USE SIGNAL ;
    PORT
      LAYER met3 ;
        RECT 418.560 542.115 419.560 542.395 ;
    END
  END dout[849]

  PIN dout[850]
    DIRECTION OUTPUT ;
    USE SIGNAL ;
    PORT
      LAYER met3 ;
        RECT 418.560 542.750 419.560 543.030 ;
    END
  END dout[850]

  PIN dout[851]
    DIRECTION OUTPUT ;
    USE SIGNAL ;
    PORT
      LAYER met3 ;
        RECT 418.560 543.385 419.560 543.665 ;
    END
  END dout[851]

  PIN dout[852]
    DIRECTION OUTPUT ;
    USE SIGNAL ;
    PORT
      LAYER met3 ;
        RECT 418.560 544.020 419.560 544.300 ;
    END
  END dout[852]

  PIN dout[853]
    DIRECTION OUTPUT ;
    USE SIGNAL ;
    PORT
      LAYER met3 ;
        RECT 418.560 544.655 419.560 544.935 ;
    END
  END dout[853]

  PIN dout[854]
    DIRECTION OUTPUT ;
    USE SIGNAL ;
    PORT
      LAYER met3 ;
        RECT 418.560 545.290 419.560 545.570 ;
    END
  END dout[854]

  PIN dout[855]
    DIRECTION OUTPUT ;
    USE SIGNAL ;
    PORT
      LAYER met3 ;
        RECT 418.560 545.925 419.560 546.205 ;
    END
  END dout[855]

  PIN dout[856]
    DIRECTION OUTPUT ;
    USE SIGNAL ;
    PORT
      LAYER met3 ;
        RECT 418.560 546.560 419.560 546.840 ;
    END
  END dout[856]

  PIN dout[857]
    DIRECTION OUTPUT ;
    USE SIGNAL ;
    PORT
      LAYER met3 ;
        RECT 418.560 547.195 419.560 547.475 ;
    END
  END dout[857]

  PIN dout[858]
    DIRECTION OUTPUT ;
    USE SIGNAL ;
    PORT
      LAYER met3 ;
        RECT 418.560 547.830 419.560 548.110 ;
    END
  END dout[858]

  PIN dout[859]
    DIRECTION OUTPUT ;
    USE SIGNAL ;
    PORT
      LAYER met3 ;
        RECT 418.560 548.465 419.560 548.745 ;
    END
  END dout[859]

  PIN dout[860]
    DIRECTION OUTPUT ;
    USE SIGNAL ;
    PORT
      LAYER met3 ;
        RECT 418.560 549.100 419.560 549.380 ;
    END
  END dout[860]

  PIN dout[861]
    DIRECTION OUTPUT ;
    USE SIGNAL ;
    PORT
      LAYER met3 ;
        RECT 418.560 549.735 419.560 550.015 ;
    END
  END dout[861]

  PIN dout[862]
    DIRECTION OUTPUT ;
    USE SIGNAL ;
    PORT
      LAYER met3 ;
        RECT 418.560 550.370 419.560 550.650 ;
    END
  END dout[862]

  PIN dout[863]
    DIRECTION OUTPUT ;
    USE SIGNAL ;
    PORT
      LAYER met3 ;
        RECT 418.560 551.005 419.560 551.285 ;
    END
  END dout[863]

  PIN dout[864]
    DIRECTION OUTPUT ;
    USE SIGNAL ;
    PORT
      LAYER met3 ;
        RECT 418.560 551.640 419.560 551.920 ;
    END
  END dout[864]

  PIN dout[865]
    DIRECTION OUTPUT ;
    USE SIGNAL ;
    PORT
      LAYER met3 ;
        RECT 418.560 552.275 419.560 552.555 ;
    END
  END dout[865]

  PIN dout[866]
    DIRECTION OUTPUT ;
    USE SIGNAL ;
    PORT
      LAYER met3 ;
        RECT 418.560 552.910 419.560 553.190 ;
    END
  END dout[866]

  PIN dout[867]
    DIRECTION OUTPUT ;
    USE SIGNAL ;
    PORT
      LAYER met3 ;
        RECT 418.560 553.545 419.560 553.825 ;
    END
  END dout[867]

  PIN dout[868]
    DIRECTION OUTPUT ;
    USE SIGNAL ;
    PORT
      LAYER met3 ;
        RECT 418.560 554.180 419.560 554.460 ;
    END
  END dout[868]

  PIN dout[869]
    DIRECTION OUTPUT ;
    USE SIGNAL ;
    PORT
      LAYER met3 ;
        RECT 418.560 554.815 419.560 555.095 ;
    END
  END dout[869]

  PIN dout[870]
    DIRECTION OUTPUT ;
    USE SIGNAL ;
    PORT
      LAYER met3 ;
        RECT 418.560 555.450 419.560 555.730 ;
    END
  END dout[870]

  PIN dout[871]
    DIRECTION OUTPUT ;
    USE SIGNAL ;
    PORT
      LAYER met3 ;
        RECT 418.560 556.085 419.560 556.365 ;
    END
  END dout[871]

  PIN dout[872]
    DIRECTION OUTPUT ;
    USE SIGNAL ;
    PORT
      LAYER met3 ;
        RECT 418.560 556.720 419.560 557.000 ;
    END
  END dout[872]

  PIN dout[873]
    DIRECTION OUTPUT ;
    USE SIGNAL ;
    PORT
      LAYER met3 ;
        RECT 418.560 557.355 419.560 557.635 ;
    END
  END dout[873]

  PIN dout[874]
    DIRECTION OUTPUT ;
    USE SIGNAL ;
    PORT
      LAYER met3 ;
        RECT 418.560 557.990 419.560 558.270 ;
    END
  END dout[874]

  PIN dout[875]
    DIRECTION OUTPUT ;
    USE SIGNAL ;
    PORT
      LAYER met3 ;
        RECT 418.560 558.625 419.560 558.905 ;
    END
  END dout[875]

  PIN dout[876]
    DIRECTION OUTPUT ;
    USE SIGNAL ;
    PORT
      LAYER met3 ;
        RECT 418.560 559.260 419.560 559.540 ;
    END
  END dout[876]

  PIN dout[877]
    DIRECTION OUTPUT ;
    USE SIGNAL ;
    PORT
      LAYER met3 ;
        RECT 418.560 559.895 419.560 560.175 ;
    END
  END dout[877]

  PIN dout[878]
    DIRECTION OUTPUT ;
    USE SIGNAL ;
    PORT
      LAYER met3 ;
        RECT 418.560 560.530 419.560 560.810 ;
    END
  END dout[878]

  PIN dout[879]
    DIRECTION OUTPUT ;
    USE SIGNAL ;
    PORT
      LAYER met3 ;
        RECT 418.560 561.165 419.560 561.445 ;
    END
  END dout[879]

  PIN VDD
    DIRECTION INOUT ;
    USE POWER ;
    PORT
      LAYER met4 ;
        RECT 0.000 564.760 419.060 565.760 ;
    END
  END VDD

  PIN VSS
    DIRECTION INOUT ;
    USE GROUND ;
    PORT
      LAYER met4 ;
        RECT 0.000 0.000 419.060 1.000 ;
    END
  END VSS

  OBS
    LAYER met1 ;
      RECT 2.000 2.000 417.060 563.760 ;
    LAYER met2 ;
      RECT 2.000 2.000 417.060 563.760 ;
  END

END nor_rom_1024x880

END LIBRARY
